# Generated by FakeRAM 2.0
VERSION 5.7 ;
BUSBITCHARS "[]" ;
PROPERTYDEFINITIONS
  MACRO width INTEGER ;
  MACRO depth INTEGER ;
  MACRO banks INTEGER ;
END PROPERTYDEFINITIONS
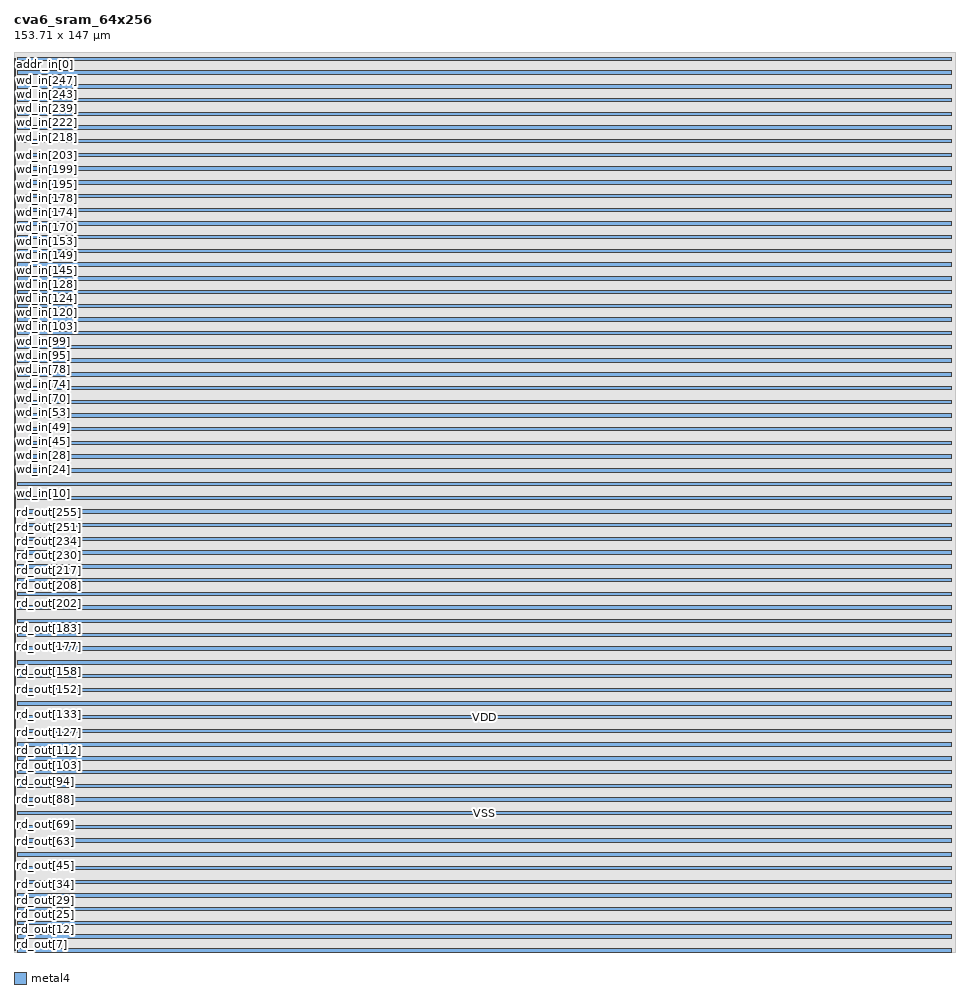
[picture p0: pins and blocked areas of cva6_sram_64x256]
MACRO cva6_sram_64x256
  PROPERTY width 256 ;
  PROPERTY depth 64 ;
  PROPERTY banks 1 ;
  FOREIGN cva6_sram_64x256 0 0 ;
  SYMMETRY X Y R90 ;
  SIZE 153.7100 BY 147.0000 ;
  CLASS BLOCK ;
  PIN rd_out[0]
    DIRECTION OUTPUT ;
    USE SIGNAL ;
    PORT
      LAYER metal4 ;
      RECT 0.00000 0.28000 0.21000 0.42000 ;
    END
  END rd_out[0]
  PIN rd_out[1]
    DIRECTION OUTPUT ;
    USE SIGNAL ;
    PORT
      LAYER metal4 ;
      RECT 0.00000 0.56000 0.21000 0.70000 ;
    END
  END rd_out[1]
  PIN rd_out[2]
    DIRECTION OUTPUT ;
    USE SIGNAL ;
    PORT
      LAYER metal4 ;
      RECT 0.00000 0.84000 0.21000 0.98000 ;
    END
  END rd_out[2]
  PIN rd_out[3]
    DIRECTION OUTPUT ;
    USE SIGNAL ;
    PORT
      LAYER metal4 ;
      RECT 0.00000 1.12000 0.21000 1.26000 ;
    END
  END rd_out[3]
  PIN rd_out[4]
    DIRECTION OUTPUT ;
    USE SIGNAL ;
    PORT
      LAYER metal4 ;
      RECT 0.00000 1.40000 0.21000 1.54000 ;
    END
  END rd_out[4]
  PIN rd_out[5]
    DIRECTION OUTPUT ;
    USE SIGNAL ;
    PORT
      LAYER metal4 ;
      RECT 0.00000 1.68000 0.21000 1.82000 ;
    END
  END rd_out[5]
  PIN rd_out[6]
    DIRECTION OUTPUT ;
    USE SIGNAL ;
    PORT
      LAYER metal4 ;
      RECT 0.00000 1.96000 0.21000 2.10000 ;
    END
  END rd_out[6]
  PIN rd_out[7]
    DIRECTION OUTPUT ;
    USE SIGNAL ;
    PORT
      LAYER metal4 ;
      RECT 0.00000 2.24000 0.21000 2.38000 ;
    END
  END rd_out[7]
  PIN rd_out[8]
    DIRECTION OUTPUT ;
    USE SIGNAL ;
    PORT
      LAYER metal4 ;
      RECT 0.00000 2.52000 0.21000 2.66000 ;
    END
  END rd_out[8]
  PIN rd_out[9]
    DIRECTION OUTPUT ;
    USE SIGNAL ;
    PORT
      LAYER metal4 ;
      RECT 0.00000 2.80000 0.21000 2.94000 ;
    END
  END rd_out[9]
  PIN rd_out[10]
    DIRECTION OUTPUT ;
    USE SIGNAL ;
    PORT
      LAYER metal4 ;
      RECT 0.00000 3.08000 0.21000 3.22000 ;
    END
  END rd_out[10]
  PIN rd_out[11]
    DIRECTION OUTPUT ;
    USE SIGNAL ;
    PORT
      LAYER metal4 ;
      RECT 0.00000 3.36000 0.21000 3.50000 ;
    END
  END rd_out[11]
  PIN rd_out[12]
    DIRECTION OUTPUT ;
    USE SIGNAL ;
    PORT
      LAYER metal4 ;
      RECT 0.00000 3.64000 0.21000 3.78000 ;
    END
  END rd_out[12]
  PIN rd_out[13]
    DIRECTION OUTPUT ;
    USE SIGNAL ;
    PORT
      LAYER metal4 ;
      RECT 0.00000 3.92000 0.21000 4.06000 ;
    END
  END rd_out[13]
  PIN rd_out[14]
    DIRECTION OUTPUT ;
    USE SIGNAL ;
    PORT
      LAYER metal4 ;
      RECT 0.00000 4.20000 0.21000 4.34000 ;
    END
  END rd_out[14]
  PIN rd_out[15]
    DIRECTION OUTPUT ;
    USE SIGNAL ;
    PORT
      LAYER metal4 ;
      RECT 0.00000 4.48000 0.21000 4.62000 ;
    END
  END rd_out[15]
  PIN rd_out[16]
    DIRECTION OUTPUT ;
    USE SIGNAL ;
    PORT
      LAYER metal4 ;
      RECT 0.00000 4.76000 0.21000 4.90000 ;
    END
  END rd_out[16]
  PIN rd_out[17]
    DIRECTION OUTPUT ;
    USE SIGNAL ;
    PORT
      LAYER metal4 ;
      RECT 0.00000 5.04000 0.21000 5.18000 ;
    END
  END rd_out[17]
  PIN rd_out[18]
    DIRECTION OUTPUT ;
    USE SIGNAL ;
    PORT
      LAYER metal4 ;
      RECT 0.00000 5.32000 0.21000 5.46000 ;
    END
  END rd_out[18]
  PIN rd_out[19]
    DIRECTION OUTPUT ;
    USE SIGNAL ;
    PORT
      LAYER metal4 ;
      RECT 0.00000 5.60000 0.21000 5.74000 ;
    END
  END rd_out[19]
  PIN rd_out[20]
    DIRECTION OUTPUT ;
    USE SIGNAL ;
    PORT
      LAYER metal4 ;
      RECT 0.00000 5.88000 0.21000 6.02000 ;
    END
  END rd_out[20]
  PIN rd_out[21]
    DIRECTION OUTPUT ;
    USE SIGNAL ;
    PORT
      LAYER metal4 ;
      RECT 0.00000 6.16000 0.21000 6.30000 ;
    END
  END rd_out[21]
  PIN rd_out[22]
    DIRECTION OUTPUT ;
    USE SIGNAL ;
    PORT
      LAYER metal4 ;
      RECT 0.00000 6.44000 0.21000 6.58000 ;
    END
  END rd_out[22]
  PIN rd_out[23]
    DIRECTION OUTPUT ;
    USE SIGNAL ;
    PORT
      LAYER metal4 ;
      RECT 0.00000 6.72000 0.21000 6.86000 ;
    END
  END rd_out[23]
  PIN rd_out[24]
    DIRECTION OUTPUT ;
    USE SIGNAL ;
    PORT
      LAYER metal4 ;
      RECT 0.00000 7.00000 0.21000 7.14000 ;
    END
  END rd_out[24]
  PIN rd_out[25]
    DIRECTION OUTPUT ;
    USE SIGNAL ;
    PORT
      LAYER metal4 ;
      RECT 0.00000 7.28000 0.21000 7.42000 ;
    END
  END rd_out[25]
  PIN rd_out[26]
    DIRECTION OUTPUT ;
    USE SIGNAL ;
    PORT
      LAYER metal4 ;
      RECT 0.00000 7.56000 0.21000 7.70000 ;
    END
  END rd_out[26]
  PIN rd_out[27]
    DIRECTION OUTPUT ;
    USE SIGNAL ;
    PORT
      LAYER metal4 ;
      RECT 0.00000 7.84000 0.21000 7.98000 ;
    END
  END rd_out[27]
  PIN rd_out[28]
    DIRECTION OUTPUT ;
    USE SIGNAL ;
    PORT
      LAYER metal4 ;
      RECT 0.00000 8.12000 0.21000 8.26000 ;
    END
  END rd_out[28]
  PIN rd_out[29]
    DIRECTION OUTPUT ;
    USE SIGNAL ;
    PORT
      LAYER metal4 ;
      RECT 0.00000 8.40000 0.21000 8.54000 ;
    END
  END rd_out[29]
  PIN rd_out[30]
    DIRECTION OUTPUT ;
    USE SIGNAL ;
    PORT
      LAYER metal4 ;
      RECT 0.00000 8.68000 0.21000 8.82000 ;
    END
  END rd_out[30]
  PIN rd_out[31]
    DIRECTION OUTPUT ;
    USE SIGNAL ;
    PORT
      LAYER metal4 ;
      RECT 0.00000 8.96000 0.21000 9.10000 ;
    END
  END rd_out[31]
  PIN rd_out[32]
    DIRECTION OUTPUT ;
    USE SIGNAL ;
    PORT
      LAYER metal4 ;
      RECT 0.00000 9.24000 0.21000 9.38000 ;
    END
  END rd_out[32]
  PIN rd_out[33]
    DIRECTION OUTPUT ;
    USE SIGNAL ;
    PORT
      LAYER metal4 ;
      RECT 0.00000 9.52000 0.21000 9.66000 ;
    END
  END rd_out[33]
  PIN rd_out[34]
    DIRECTION OUTPUT ;
    USE SIGNAL ;
    PORT
      LAYER metal4 ;
      RECT 0.00000 9.80000 0.21000 9.94000 ;
    END
  END rd_out[34]
  PIN rd_out[35]
    DIRECTION OUTPUT ;
    USE SIGNAL ;
    PORT
      LAYER metal4 ;
      RECT 0.00000 10.08000 0.21000 10.22000 ;
    END
  END rd_out[35]
  PIN rd_out[36]
    DIRECTION OUTPUT ;
    USE SIGNAL ;
    PORT
      LAYER metal4 ;
      RECT 0.00000 10.36000 0.21000 10.50000 ;
    END
  END rd_out[36]
  PIN rd_out[37]
    DIRECTION OUTPUT ;
    USE SIGNAL ;
    PORT
      LAYER metal4 ;
      RECT 0.00000 10.64000 0.21000 10.78000 ;
    END
  END rd_out[37]
  PIN rd_out[38]
    DIRECTION OUTPUT ;
    USE SIGNAL ;
    PORT
      LAYER metal4 ;
      RECT 0.00000 10.92000 0.21000 11.06000 ;
    END
  END rd_out[38]
  PIN rd_out[39]
    DIRECTION OUTPUT ;
    USE SIGNAL ;
    PORT
      LAYER metal4 ;
      RECT 0.00000 11.20000 0.21000 11.34000 ;
    END
  END rd_out[39]
  PIN rd_out[40]
    DIRECTION OUTPUT ;
    USE SIGNAL ;
    PORT
      LAYER metal4 ;
      RECT 0.00000 11.48000 0.21000 11.62000 ;
    END
  END rd_out[40]
  PIN rd_out[41]
    DIRECTION OUTPUT ;
    USE SIGNAL ;
    PORT
      LAYER metal4 ;
      RECT 0.00000 11.76000 0.21000 11.90000 ;
    END
  END rd_out[41]
  PIN rd_out[42]
    DIRECTION OUTPUT ;
    USE SIGNAL ;
    PORT
      LAYER metal4 ;
      RECT 0.00000 12.04000 0.21000 12.18000 ;
    END
  END rd_out[42]
  PIN rd_out[43]
    DIRECTION OUTPUT ;
    USE SIGNAL ;
    PORT
      LAYER metal4 ;
      RECT 0.00000 12.32000 0.21000 12.46000 ;
    END
  END rd_out[43]
  PIN rd_out[44]
    DIRECTION OUTPUT ;
    USE SIGNAL ;
    PORT
      LAYER metal4 ;
      RECT 0.00000 12.60000 0.21000 12.74000 ;
    END
  END rd_out[44]
  PIN rd_out[45]
    DIRECTION OUTPUT ;
    USE SIGNAL ;
    PORT
      LAYER metal4 ;
      RECT 0.00000 12.88000 0.21000 13.02000 ;
    END
  END rd_out[45]
  PIN rd_out[46]
    DIRECTION OUTPUT ;
    USE SIGNAL ;
    PORT
      LAYER metal4 ;
      RECT 0.00000 13.16000 0.21000 13.30000 ;
    END
  END rd_out[46]
  PIN rd_out[47]
    DIRECTION OUTPUT ;
    USE SIGNAL ;
    PORT
      LAYER metal4 ;
      RECT 0.00000 13.44000 0.21000 13.58000 ;
    END
  END rd_out[47]
  PIN rd_out[48]
    DIRECTION OUTPUT ;
    USE SIGNAL ;
    PORT
      LAYER metal4 ;
      RECT 0.00000 13.72000 0.21000 13.86000 ;
    END
  END rd_out[48]
  PIN rd_out[49]
    DIRECTION OUTPUT ;
    USE SIGNAL ;
    PORT
      LAYER metal4 ;
      RECT 0.00000 14.00000 0.21000 14.14000 ;
    END
  END rd_out[49]
  PIN rd_out[50]
    DIRECTION OUTPUT ;
    USE SIGNAL ;
    PORT
      LAYER metal4 ;
      RECT 0.00000 14.28000 0.21000 14.42000 ;
    END
  END rd_out[50]
  PIN rd_out[51]
    DIRECTION OUTPUT ;
    USE SIGNAL ;
    PORT
      LAYER metal4 ;
      RECT 0.00000 14.56000 0.21000 14.70000 ;
    END
  END rd_out[51]
  PIN rd_out[52]
    DIRECTION OUTPUT ;
    USE SIGNAL ;
    PORT
      LAYER metal4 ;
      RECT 0.00000 14.84000 0.21000 14.98000 ;
    END
  END rd_out[52]
  PIN rd_out[53]
    DIRECTION OUTPUT ;
    USE SIGNAL ;
    PORT
      LAYER metal4 ;
      RECT 0.00000 15.12000 0.21000 15.26000 ;
    END
  END rd_out[53]
  PIN rd_out[54]
    DIRECTION OUTPUT ;
    USE SIGNAL ;
    PORT
      LAYER metal4 ;
      RECT 0.00000 15.40000 0.21000 15.54000 ;
    END
  END rd_out[54]
  PIN rd_out[55]
    DIRECTION OUTPUT ;
    USE SIGNAL ;
    PORT
      LAYER metal4 ;
      RECT 0.00000 15.68000 0.21000 15.82000 ;
    END
  END rd_out[55]
  PIN rd_out[56]
    DIRECTION OUTPUT ;
    USE SIGNAL ;
    PORT
      LAYER metal4 ;
      RECT 0.00000 15.96000 0.21000 16.10000 ;
    END
  END rd_out[56]
  PIN rd_out[57]
    DIRECTION OUTPUT ;
    USE SIGNAL ;
    PORT
      LAYER metal4 ;
      RECT 0.00000 16.24000 0.21000 16.38000 ;
    END
  END rd_out[57]
  PIN rd_out[58]
    DIRECTION OUTPUT ;
    USE SIGNAL ;
    PORT
      LAYER metal4 ;
      RECT 0.00000 16.52000 0.21000 16.66000 ;
    END
  END rd_out[58]
  PIN rd_out[59]
    DIRECTION OUTPUT ;
    USE SIGNAL ;
    PORT
      LAYER metal4 ;
      RECT 0.00000 16.80000 0.21000 16.94000 ;
    END
  END rd_out[59]
  PIN rd_out[60]
    DIRECTION OUTPUT ;
    USE SIGNAL ;
    PORT
      LAYER metal4 ;
      RECT 0.00000 17.08000 0.21000 17.22000 ;
    END
  END rd_out[60]
  PIN rd_out[61]
    DIRECTION OUTPUT ;
    USE SIGNAL ;
    PORT
      LAYER metal4 ;
      RECT 0.00000 17.36000 0.21000 17.50000 ;
    END
  END rd_out[61]
  PIN rd_out[62]
    DIRECTION OUTPUT ;
    USE SIGNAL ;
    PORT
      LAYER metal4 ;
      RECT 0.00000 17.64000 0.21000 17.78000 ;
    END
  END rd_out[62]
  PIN rd_out[63]
    DIRECTION OUTPUT ;
    USE SIGNAL ;
    PORT
      LAYER metal4 ;
      RECT 0.00000 17.92000 0.21000 18.06000 ;
    END
  END rd_out[63]
  PIN rd_out[64]
    DIRECTION OUTPUT ;
    USE SIGNAL ;
    PORT
      LAYER metal4 ;
      RECT 0.00000 18.20000 0.21000 18.34000 ;
    END
  END rd_out[64]
  PIN rd_out[65]
    DIRECTION OUTPUT ;
    USE SIGNAL ;
    PORT
      LAYER metal4 ;
      RECT 0.00000 18.48000 0.21000 18.62000 ;
    END
  END rd_out[65]
  PIN rd_out[66]
    DIRECTION OUTPUT ;
    USE SIGNAL ;
    PORT
      LAYER metal4 ;
      RECT 0.00000 18.76000 0.21000 18.90000 ;
    END
  END rd_out[66]
  PIN rd_out[67]
    DIRECTION OUTPUT ;
    USE SIGNAL ;
    PORT
      LAYER metal4 ;
      RECT 0.00000 19.04000 0.21000 19.18000 ;
    END
  END rd_out[67]
  PIN rd_out[68]
    DIRECTION OUTPUT ;
    USE SIGNAL ;
    PORT
      LAYER metal4 ;
      RECT 0.00000 19.32000 0.21000 19.46000 ;
    END
  END rd_out[68]
  PIN rd_out[69]
    DIRECTION OUTPUT ;
    USE SIGNAL ;
    PORT
      LAYER metal4 ;
      RECT 0.00000 19.60000 0.21000 19.74000 ;
    END
  END rd_out[69]
  PIN rd_out[70]
    DIRECTION OUTPUT ;
    USE SIGNAL ;
    PORT
      LAYER metal4 ;
      RECT 0.00000 19.88000 0.21000 20.02000 ;
    END
  END rd_out[70]
  PIN rd_out[71]
    DIRECTION OUTPUT ;
    USE SIGNAL ;
    PORT
      LAYER metal4 ;
      RECT 0.00000 20.16000 0.21000 20.30000 ;
    END
  END rd_out[71]
  PIN rd_out[72]
    DIRECTION OUTPUT ;
    USE SIGNAL ;
    PORT
      LAYER metal4 ;
      RECT 0.00000 20.44000 0.21000 20.58000 ;
    END
  END rd_out[72]
  PIN rd_out[73]
    DIRECTION OUTPUT ;
    USE SIGNAL ;
    PORT
      LAYER metal4 ;
      RECT 0.00000 20.72000 0.21000 20.86000 ;
    END
  END rd_out[73]
  PIN rd_out[74]
    DIRECTION OUTPUT ;
    USE SIGNAL ;
    PORT
      LAYER metal4 ;
      RECT 0.00000 21.00000 0.21000 21.14000 ;
    END
  END rd_out[74]
  PIN rd_out[75]
    DIRECTION OUTPUT ;
    USE SIGNAL ;
    PORT
      LAYER metal4 ;
      RECT 0.00000 21.28000 0.21000 21.42000 ;
    END
  END rd_out[75]
  PIN rd_out[76]
    DIRECTION OUTPUT ;
    USE SIGNAL ;
    PORT
      LAYER metal4 ;
      RECT 0.00000 21.56000 0.21000 21.70000 ;
    END
  END rd_out[76]
  PIN rd_out[77]
    DIRECTION OUTPUT ;
    USE SIGNAL ;
    PORT
      LAYER metal4 ;
      RECT 0.00000 21.84000 0.21000 21.98000 ;
    END
  END rd_out[77]
  PIN rd_out[78]
    DIRECTION OUTPUT ;
    USE SIGNAL ;
    PORT
      LAYER metal4 ;
      RECT 0.00000 22.12000 0.21000 22.26000 ;
    END
  END rd_out[78]
  PIN rd_out[79]
    DIRECTION OUTPUT ;
    USE SIGNAL ;
    PORT
      LAYER metal4 ;
      RECT 0.00000 22.40000 0.21000 22.54000 ;
    END
  END rd_out[79]
  PIN rd_out[80]
    DIRECTION OUTPUT ;
    USE SIGNAL ;
    PORT
      LAYER metal4 ;
      RECT 0.00000 22.68000 0.21000 22.82000 ;
    END
  END rd_out[80]
  PIN rd_out[81]
    DIRECTION OUTPUT ;
    USE SIGNAL ;
    PORT
      LAYER metal4 ;
      RECT 0.00000 22.96000 0.21000 23.10000 ;
    END
  END rd_out[81]
  PIN rd_out[82]
    DIRECTION OUTPUT ;
    USE SIGNAL ;
    PORT
      LAYER metal4 ;
      RECT 0.00000 23.24000 0.21000 23.38000 ;
    END
  END rd_out[82]
  PIN rd_out[83]
    DIRECTION OUTPUT ;
    USE SIGNAL ;
    PORT
      LAYER metal4 ;
      RECT 0.00000 23.52000 0.21000 23.66000 ;
    END
  END rd_out[83]
  PIN rd_out[84]
    DIRECTION OUTPUT ;
    USE SIGNAL ;
    PORT
      LAYER metal4 ;
      RECT 0.00000 23.80000 0.21000 23.94000 ;
    END
  END rd_out[84]
  PIN rd_out[85]
    DIRECTION OUTPUT ;
    USE SIGNAL ;
    PORT
      LAYER metal4 ;
      RECT 0.00000 24.08000 0.21000 24.22000 ;
    END
  END rd_out[85]
  PIN rd_out[86]
    DIRECTION OUTPUT ;
    USE SIGNAL ;
    PORT
      LAYER metal4 ;
      RECT 0.00000 24.36000 0.21000 24.50000 ;
    END
  END rd_out[86]
  PIN rd_out[87]
    DIRECTION OUTPUT ;
    USE SIGNAL ;
    PORT
      LAYER metal4 ;
      RECT 0.00000 24.64000 0.21000 24.78000 ;
    END
  END rd_out[87]
  PIN rd_out[88]
    DIRECTION OUTPUT ;
    USE SIGNAL ;
    PORT
      LAYER metal4 ;
      RECT 0.00000 24.92000 0.21000 25.06000 ;
    END
  END rd_out[88]
  PIN rd_out[89]
    DIRECTION OUTPUT ;
    USE SIGNAL ;
    PORT
      LAYER metal4 ;
      RECT 0.00000 25.20000 0.21000 25.34000 ;
    END
  END rd_out[89]
  PIN rd_out[90]
    DIRECTION OUTPUT ;
    USE SIGNAL ;
    PORT
      LAYER metal4 ;
      RECT 0.00000 25.48000 0.21000 25.62000 ;
    END
  END rd_out[90]
  PIN rd_out[91]
    DIRECTION OUTPUT ;
    USE SIGNAL ;
    PORT
      LAYER metal4 ;
      RECT 0.00000 25.76000 0.21000 25.90000 ;
    END
  END rd_out[91]
  PIN rd_out[92]
    DIRECTION OUTPUT ;
    USE SIGNAL ;
    PORT
      LAYER metal4 ;
      RECT 0.00000 26.04000 0.21000 26.18000 ;
    END
  END rd_out[92]
  PIN rd_out[93]
    DIRECTION OUTPUT ;
    USE SIGNAL ;
    PORT
      LAYER metal4 ;
      RECT 0.00000 26.32000 0.21000 26.46000 ;
    END
  END rd_out[93]
  PIN rd_out[94]
    DIRECTION OUTPUT ;
    USE SIGNAL ;
    PORT
      LAYER metal4 ;
      RECT 0.00000 26.60000 0.21000 26.74000 ;
    END
  END rd_out[94]
  PIN rd_out[95]
    DIRECTION OUTPUT ;
    USE SIGNAL ;
    PORT
      LAYER metal4 ;
      RECT 0.00000 26.88000 0.21000 27.02000 ;
    END
  END rd_out[95]
  PIN rd_out[96]
    DIRECTION OUTPUT ;
    USE SIGNAL ;
    PORT
      LAYER metal4 ;
      RECT 0.00000 27.16000 0.21000 27.30000 ;
    END
  END rd_out[96]
  PIN rd_out[97]
    DIRECTION OUTPUT ;
    USE SIGNAL ;
    PORT
      LAYER metal4 ;
      RECT 0.00000 27.44000 0.21000 27.58000 ;
    END
  END rd_out[97]
  PIN rd_out[98]
    DIRECTION OUTPUT ;
    USE SIGNAL ;
    PORT
      LAYER metal4 ;
      RECT 0.00000 27.72000 0.21000 27.86000 ;
    END
  END rd_out[98]
  PIN rd_out[99]
    DIRECTION OUTPUT ;
    USE SIGNAL ;
    PORT
      LAYER metal4 ;
      RECT 0.00000 28.00000 0.21000 28.14000 ;
    END
  END rd_out[99]
  PIN rd_out[100]
    DIRECTION OUTPUT ;
    USE SIGNAL ;
    PORT
      LAYER metal4 ;
      RECT 0.00000 28.28000 0.21000 28.42000 ;
    END
  END rd_out[100]
  PIN rd_out[101]
    DIRECTION OUTPUT ;
    USE SIGNAL ;
    PORT
      LAYER metal4 ;
      RECT 0.00000 28.56000 0.21000 28.70000 ;
    END
  END rd_out[101]
  PIN rd_out[102]
    DIRECTION OUTPUT ;
    USE SIGNAL ;
    PORT
      LAYER metal4 ;
      RECT 0.00000 28.84000 0.21000 28.98000 ;
    END
  END rd_out[102]
  PIN rd_out[103]
    DIRECTION OUTPUT ;
    USE SIGNAL ;
    PORT
      LAYER metal4 ;
      RECT 0.00000 29.12000 0.21000 29.26000 ;
    END
  END rd_out[103]
  PIN rd_out[104]
    DIRECTION OUTPUT ;
    USE SIGNAL ;
    PORT
      LAYER metal4 ;
      RECT 0.00000 29.40000 0.21000 29.54000 ;
    END
  END rd_out[104]
  PIN rd_out[105]
    DIRECTION OUTPUT ;
    USE SIGNAL ;
    PORT
      LAYER metal4 ;
      RECT 0.00000 29.68000 0.21000 29.82000 ;
    END
  END rd_out[105]
  PIN rd_out[106]
    DIRECTION OUTPUT ;
    USE SIGNAL ;
    PORT
      LAYER metal4 ;
      RECT 0.00000 29.96000 0.21000 30.10000 ;
    END
  END rd_out[106]
  PIN rd_out[107]
    DIRECTION OUTPUT ;
    USE SIGNAL ;
    PORT
      LAYER metal4 ;
      RECT 0.00000 30.24000 0.21000 30.38000 ;
    END
  END rd_out[107]
  PIN rd_out[108]
    DIRECTION OUTPUT ;
    USE SIGNAL ;
    PORT
      LAYER metal4 ;
      RECT 0.00000 30.52000 0.21000 30.66000 ;
    END
  END rd_out[108]
  PIN rd_out[109]
    DIRECTION OUTPUT ;
    USE SIGNAL ;
    PORT
      LAYER metal4 ;
      RECT 0.00000 30.80000 0.21000 30.94000 ;
    END
  END rd_out[109]
  PIN rd_out[110]
    DIRECTION OUTPUT ;
    USE SIGNAL ;
    PORT
      LAYER metal4 ;
      RECT 0.00000 31.08000 0.21000 31.22000 ;
    END
  END rd_out[110]
  PIN rd_out[111]
    DIRECTION OUTPUT ;
    USE SIGNAL ;
    PORT
      LAYER metal4 ;
      RECT 0.00000 31.36000 0.21000 31.50000 ;
    END
  END rd_out[111]
  PIN rd_out[112]
    DIRECTION OUTPUT ;
    USE SIGNAL ;
    PORT
      LAYER metal4 ;
      RECT 0.00000 31.64000 0.21000 31.78000 ;
    END
  END rd_out[112]
  PIN rd_out[113]
    DIRECTION OUTPUT ;
    USE SIGNAL ;
    PORT
      LAYER metal4 ;
      RECT 0.00000 31.92000 0.21000 32.06000 ;
    END
  END rd_out[113]
  PIN rd_out[114]
    DIRECTION OUTPUT ;
    USE SIGNAL ;
    PORT
      LAYER metal4 ;
      RECT 0.00000 32.20000 0.21000 32.34000 ;
    END
  END rd_out[114]
  PIN rd_out[115]
    DIRECTION OUTPUT ;
    USE SIGNAL ;
    PORT
      LAYER metal4 ;
      RECT 0.00000 32.48000 0.21000 32.62000 ;
    END
  END rd_out[115]
  PIN rd_out[116]
    DIRECTION OUTPUT ;
    USE SIGNAL ;
    PORT
      LAYER metal4 ;
      RECT 0.00000 32.76000 0.21000 32.90000 ;
    END
  END rd_out[116]
  PIN rd_out[117]
    DIRECTION OUTPUT ;
    USE SIGNAL ;
    PORT
      LAYER metal4 ;
      RECT 0.00000 33.04000 0.21000 33.18000 ;
    END
  END rd_out[117]
  PIN rd_out[118]
    DIRECTION OUTPUT ;
    USE SIGNAL ;
    PORT
      LAYER metal4 ;
      RECT 0.00000 33.32000 0.21000 33.46000 ;
    END
  END rd_out[118]
  PIN rd_out[119]
    DIRECTION OUTPUT ;
    USE SIGNAL ;
    PORT
      LAYER metal4 ;
      RECT 0.00000 33.60000 0.21000 33.74000 ;
    END
  END rd_out[119]
  PIN rd_out[120]
    DIRECTION OUTPUT ;
    USE SIGNAL ;
    PORT
      LAYER metal4 ;
      RECT 0.00000 33.88000 0.21000 34.02000 ;
    END
  END rd_out[120]
  PIN rd_out[121]
    DIRECTION OUTPUT ;
    USE SIGNAL ;
    PORT
      LAYER metal4 ;
      RECT 0.00000 34.16000 0.21000 34.30000 ;
    END
  END rd_out[121]
  PIN rd_out[122]
    DIRECTION OUTPUT ;
    USE SIGNAL ;
    PORT
      LAYER metal4 ;
      RECT 0.00000 34.44000 0.21000 34.58000 ;
    END
  END rd_out[122]
  PIN rd_out[123]
    DIRECTION OUTPUT ;
    USE SIGNAL ;
    PORT
      LAYER metal4 ;
      RECT 0.00000 34.72000 0.21000 34.86000 ;
    END
  END rd_out[123]
  PIN rd_out[124]
    DIRECTION OUTPUT ;
    USE SIGNAL ;
    PORT
      LAYER metal4 ;
      RECT 0.00000 35.00000 0.21000 35.14000 ;
    END
  END rd_out[124]
  PIN rd_out[125]
    DIRECTION OUTPUT ;
    USE SIGNAL ;
    PORT
      LAYER metal4 ;
      RECT 0.00000 35.28000 0.21000 35.42000 ;
    END
  END rd_out[125]
  PIN rd_out[126]
    DIRECTION OUTPUT ;
    USE SIGNAL ;
    PORT
      LAYER metal4 ;
      RECT 0.00000 35.56000 0.21000 35.70000 ;
    END
  END rd_out[126]
  PIN rd_out[127]
    DIRECTION OUTPUT ;
    USE SIGNAL ;
    PORT
      LAYER metal4 ;
      RECT 0.00000 35.84000 0.21000 35.98000 ;
    END
  END rd_out[127]
  PIN rd_out[128]
    DIRECTION OUTPUT ;
    USE SIGNAL ;
    PORT
      LAYER metal4 ;
      RECT 0.00000 36.12000 0.21000 36.26000 ;
    END
  END rd_out[128]
  PIN rd_out[129]
    DIRECTION OUTPUT ;
    USE SIGNAL ;
    PORT
      LAYER metal4 ;
      RECT 0.00000 36.40000 0.21000 36.54000 ;
    END
  END rd_out[129]
  PIN rd_out[130]
    DIRECTION OUTPUT ;
    USE SIGNAL ;
    PORT
      LAYER metal4 ;
      RECT 0.00000 36.68000 0.21000 36.82000 ;
    END
  END rd_out[130]
  PIN rd_out[131]
    DIRECTION OUTPUT ;
    USE SIGNAL ;
    PORT
      LAYER metal4 ;
      RECT 0.00000 36.96000 0.21000 37.10000 ;
    END
  END rd_out[131]
  PIN rd_out[132]
    DIRECTION OUTPUT ;
    USE SIGNAL ;
    PORT
      LAYER metal4 ;
      RECT 0.00000 37.24000 0.21000 37.38000 ;
    END
  END rd_out[132]
  PIN rd_out[133]
    DIRECTION OUTPUT ;
    USE SIGNAL ;
    PORT
      LAYER metal4 ;
      RECT 0.00000 37.52000 0.21000 37.66000 ;
    END
  END rd_out[133]
  PIN rd_out[134]
    DIRECTION OUTPUT ;
    USE SIGNAL ;
    PORT
      LAYER metal4 ;
      RECT 0.00000 37.80000 0.21000 37.94000 ;
    END
  END rd_out[134]
  PIN rd_out[135]
    DIRECTION OUTPUT ;
    USE SIGNAL ;
    PORT
      LAYER metal4 ;
      RECT 0.00000 38.08000 0.21000 38.22000 ;
    END
  END rd_out[135]
  PIN rd_out[136]
    DIRECTION OUTPUT ;
    USE SIGNAL ;
    PORT
      LAYER metal4 ;
      RECT 0.00000 38.36000 0.21000 38.50000 ;
    END
  END rd_out[136]
  PIN rd_out[137]
    DIRECTION OUTPUT ;
    USE SIGNAL ;
    PORT
      LAYER metal4 ;
      RECT 0.00000 38.64000 0.21000 38.78000 ;
    END
  END rd_out[137]
  PIN rd_out[138]
    DIRECTION OUTPUT ;
    USE SIGNAL ;
    PORT
      LAYER metal4 ;
      RECT 0.00000 38.92000 0.21000 39.06000 ;
    END
  END rd_out[138]
  PIN rd_out[139]
    DIRECTION OUTPUT ;
    USE SIGNAL ;
    PORT
      LAYER metal4 ;
      RECT 0.00000 39.20000 0.21000 39.34000 ;
    END
  END rd_out[139]
  PIN rd_out[140]
    DIRECTION OUTPUT ;
    USE SIGNAL ;
    PORT
      LAYER metal4 ;
      RECT 0.00000 39.48000 0.21000 39.62000 ;
    END
  END rd_out[140]
  PIN rd_out[141]
    DIRECTION OUTPUT ;
    USE SIGNAL ;
    PORT
      LAYER metal4 ;
      RECT 0.00000 39.76000 0.21000 39.90000 ;
    END
  END rd_out[141]
  PIN rd_out[142]
    DIRECTION OUTPUT ;
    USE SIGNAL ;
    PORT
      LAYER metal4 ;
      RECT 0.00000 40.04000 0.21000 40.18000 ;
    END
  END rd_out[142]
  PIN rd_out[143]
    DIRECTION OUTPUT ;
    USE SIGNAL ;
    PORT
      LAYER metal4 ;
      RECT 0.00000 40.32000 0.21000 40.46000 ;
    END
  END rd_out[143]
  PIN rd_out[144]
    DIRECTION OUTPUT ;
    USE SIGNAL ;
    PORT
      LAYER metal4 ;
      RECT 0.00000 40.60000 0.21000 40.74000 ;
    END
  END rd_out[144]
  PIN rd_out[145]
    DIRECTION OUTPUT ;
    USE SIGNAL ;
    PORT
      LAYER metal4 ;
      RECT 0.00000 40.88000 0.21000 41.02000 ;
    END
  END rd_out[145]
  PIN rd_out[146]
    DIRECTION OUTPUT ;
    USE SIGNAL ;
    PORT
      LAYER metal4 ;
      RECT 0.00000 41.16000 0.21000 41.30000 ;
    END
  END rd_out[146]
  PIN rd_out[147]
    DIRECTION OUTPUT ;
    USE SIGNAL ;
    PORT
      LAYER metal4 ;
      RECT 0.00000 41.44000 0.21000 41.58000 ;
    END
  END rd_out[147]
  PIN rd_out[148]
    DIRECTION OUTPUT ;
    USE SIGNAL ;
    PORT
      LAYER metal4 ;
      RECT 0.00000 41.72000 0.21000 41.86000 ;
    END
  END rd_out[148]
  PIN rd_out[149]
    DIRECTION OUTPUT ;
    USE SIGNAL ;
    PORT
      LAYER metal4 ;
      RECT 0.00000 42.00000 0.21000 42.14000 ;
    END
  END rd_out[149]
  PIN rd_out[150]
    DIRECTION OUTPUT ;
    USE SIGNAL ;
    PORT
      LAYER metal4 ;
      RECT 0.00000 42.28000 0.21000 42.42000 ;
    END
  END rd_out[150]
  PIN rd_out[151]
    DIRECTION OUTPUT ;
    USE SIGNAL ;
    PORT
      LAYER metal4 ;
      RECT 0.00000 42.56000 0.21000 42.70000 ;
    END
  END rd_out[151]
  PIN rd_out[152]
    DIRECTION OUTPUT ;
    USE SIGNAL ;
    PORT
      LAYER metal4 ;
      RECT 0.00000 42.84000 0.21000 42.98000 ;
    END
  END rd_out[152]
  PIN rd_out[153]
    DIRECTION OUTPUT ;
    USE SIGNAL ;
    PORT
      LAYER metal4 ;
      RECT 0.00000 43.12000 0.21000 43.26000 ;
    END
  END rd_out[153]
  PIN rd_out[154]
    DIRECTION OUTPUT ;
    USE SIGNAL ;
    PORT
      LAYER metal4 ;
      RECT 0.00000 43.40000 0.21000 43.54000 ;
    END
  END rd_out[154]
  PIN rd_out[155]
    DIRECTION OUTPUT ;
    USE SIGNAL ;
    PORT
      LAYER metal4 ;
      RECT 0.00000 43.68000 0.21000 43.82000 ;
    END
  END rd_out[155]
  PIN rd_out[156]
    DIRECTION OUTPUT ;
    USE SIGNAL ;
    PORT
      LAYER metal4 ;
      RECT 0.00000 43.96000 0.21000 44.10000 ;
    END
  END rd_out[156]
  PIN rd_out[157]
    DIRECTION OUTPUT ;
    USE SIGNAL ;
    PORT
      LAYER metal4 ;
      RECT 0.00000 44.24000 0.21000 44.38000 ;
    END
  END rd_out[157]
  PIN rd_out[158]
    DIRECTION OUTPUT ;
    USE SIGNAL ;
    PORT
      LAYER metal4 ;
      RECT 0.00000 44.52000 0.21000 44.66000 ;
    END
  END rd_out[158]
  PIN rd_out[159]
    DIRECTION OUTPUT ;
    USE SIGNAL ;
    PORT
      LAYER metal4 ;
      RECT 0.00000 44.80000 0.21000 44.94000 ;
    END
  END rd_out[159]
  PIN rd_out[160]
    DIRECTION OUTPUT ;
    USE SIGNAL ;
    PORT
      LAYER metal4 ;
      RECT 0.00000 45.08000 0.21000 45.22000 ;
    END
  END rd_out[160]
  PIN rd_out[161]
    DIRECTION OUTPUT ;
    USE SIGNAL ;
    PORT
      LAYER metal4 ;
      RECT 0.00000 45.36000 0.21000 45.50000 ;
    END
  END rd_out[161]
  PIN rd_out[162]
    DIRECTION OUTPUT ;
    USE SIGNAL ;
    PORT
      LAYER metal4 ;
      RECT 0.00000 45.64000 0.21000 45.78000 ;
    END
  END rd_out[162]
  PIN rd_out[163]
    DIRECTION OUTPUT ;
    USE SIGNAL ;
    PORT
      LAYER metal4 ;
      RECT 0.00000 45.92000 0.21000 46.06000 ;
    END
  END rd_out[163]
  PIN rd_out[164]
    DIRECTION OUTPUT ;
    USE SIGNAL ;
    PORT
      LAYER metal4 ;
      RECT 0.00000 46.20000 0.21000 46.34000 ;
    END
  END rd_out[164]
  PIN rd_out[165]
    DIRECTION OUTPUT ;
    USE SIGNAL ;
    PORT
      LAYER metal4 ;
      RECT 0.00000 46.48000 0.21000 46.62000 ;
    END
  END rd_out[165]
  PIN rd_out[166]
    DIRECTION OUTPUT ;
    USE SIGNAL ;
    PORT
      LAYER metal4 ;
      RECT 0.00000 46.76000 0.21000 46.90000 ;
    END
  END rd_out[166]
  PIN rd_out[167]
    DIRECTION OUTPUT ;
    USE SIGNAL ;
    PORT
      LAYER metal4 ;
      RECT 0.00000 47.04000 0.21000 47.18000 ;
    END
  END rd_out[167]
  PIN rd_out[168]
    DIRECTION OUTPUT ;
    USE SIGNAL ;
    PORT
      LAYER metal4 ;
      RECT 0.00000 47.32000 0.21000 47.46000 ;
    END
  END rd_out[168]
  PIN rd_out[169]
    DIRECTION OUTPUT ;
    USE SIGNAL ;
    PORT
      LAYER metal4 ;
      RECT 0.00000 47.60000 0.21000 47.74000 ;
    END
  END rd_out[169]
  PIN rd_out[170]
    DIRECTION OUTPUT ;
    USE SIGNAL ;
    PORT
      LAYER metal4 ;
      RECT 0.00000 47.88000 0.21000 48.02000 ;
    END
  END rd_out[170]
  PIN rd_out[171]
    DIRECTION OUTPUT ;
    USE SIGNAL ;
    PORT
      LAYER metal4 ;
      RECT 0.00000 48.16000 0.21000 48.30000 ;
    END
  END rd_out[171]
  PIN rd_out[172]
    DIRECTION OUTPUT ;
    USE SIGNAL ;
    PORT
      LAYER metal4 ;
      RECT 0.00000 48.44000 0.21000 48.58000 ;
    END
  END rd_out[172]
  PIN rd_out[173]
    DIRECTION OUTPUT ;
    USE SIGNAL ;
    PORT
      LAYER metal4 ;
      RECT 0.00000 48.72000 0.21000 48.86000 ;
    END
  END rd_out[173]
  PIN rd_out[174]
    DIRECTION OUTPUT ;
    USE SIGNAL ;
    PORT
      LAYER metal4 ;
      RECT 0.00000 49.00000 0.21000 49.14000 ;
    END
  END rd_out[174]
  PIN rd_out[175]
    DIRECTION OUTPUT ;
    USE SIGNAL ;
    PORT
      LAYER metal4 ;
      RECT 0.00000 49.28000 0.21000 49.42000 ;
    END
  END rd_out[175]
  PIN rd_out[176]
    DIRECTION OUTPUT ;
    USE SIGNAL ;
    PORT
      LAYER metal4 ;
      RECT 0.00000 49.56000 0.21000 49.70000 ;
    END
  END rd_out[176]
  PIN rd_out[177]
    DIRECTION OUTPUT ;
    USE SIGNAL ;
    PORT
      LAYER metal4 ;
      RECT 0.00000 49.84000 0.21000 49.98000 ;
    END
  END rd_out[177]
  PIN rd_out[178]
    DIRECTION OUTPUT ;
    USE SIGNAL ;
    PORT
      LAYER metal4 ;
      RECT 0.00000 50.12000 0.21000 50.26000 ;
    END
  END rd_out[178]
  PIN rd_out[179]
    DIRECTION OUTPUT ;
    USE SIGNAL ;
    PORT
      LAYER metal4 ;
      RECT 0.00000 50.40000 0.21000 50.54000 ;
    END
  END rd_out[179]
  PIN rd_out[180]
    DIRECTION OUTPUT ;
    USE SIGNAL ;
    PORT
      LAYER metal4 ;
      RECT 0.00000 50.68000 0.21000 50.82000 ;
    END
  END rd_out[180]
  PIN rd_out[181]
    DIRECTION OUTPUT ;
    USE SIGNAL ;
    PORT
      LAYER metal4 ;
      RECT 0.00000 50.96000 0.21000 51.10000 ;
    END
  END rd_out[181]
  PIN rd_out[182]
    DIRECTION OUTPUT ;
    USE SIGNAL ;
    PORT
      LAYER metal4 ;
      RECT 0.00000 51.24000 0.21000 51.38000 ;
    END
  END rd_out[182]
  PIN rd_out[183]
    DIRECTION OUTPUT ;
    USE SIGNAL ;
    PORT
      LAYER metal4 ;
      RECT 0.00000 51.52000 0.21000 51.66000 ;
    END
  END rd_out[183]
  PIN rd_out[184]
    DIRECTION OUTPUT ;
    USE SIGNAL ;
    PORT
      LAYER metal4 ;
      RECT 0.00000 51.80000 0.21000 51.94000 ;
    END
  END rd_out[184]
  PIN rd_out[185]
    DIRECTION OUTPUT ;
    USE SIGNAL ;
    PORT
      LAYER metal4 ;
      RECT 0.00000 52.08000 0.21000 52.22000 ;
    END
  END rd_out[185]
  PIN rd_out[186]
    DIRECTION OUTPUT ;
    USE SIGNAL ;
    PORT
      LAYER metal4 ;
      RECT 0.00000 52.36000 0.21000 52.50000 ;
    END
  END rd_out[186]
  PIN rd_out[187]
    DIRECTION OUTPUT ;
    USE SIGNAL ;
    PORT
      LAYER metal4 ;
      RECT 0.00000 52.64000 0.21000 52.78000 ;
    END
  END rd_out[187]
  PIN rd_out[188]
    DIRECTION OUTPUT ;
    USE SIGNAL ;
    PORT
      LAYER metal4 ;
      RECT 0.00000 52.92000 0.21000 53.06000 ;
    END
  END rd_out[188]
  PIN rd_out[189]
    DIRECTION OUTPUT ;
    USE SIGNAL ;
    PORT
      LAYER metal4 ;
      RECT 0.00000 53.20000 0.21000 53.34000 ;
    END
  END rd_out[189]
  PIN rd_out[190]
    DIRECTION OUTPUT ;
    USE SIGNAL ;
    PORT
      LAYER metal4 ;
      RECT 0.00000 53.48000 0.21000 53.62000 ;
    END
  END rd_out[190]
  PIN rd_out[191]
    DIRECTION OUTPUT ;
    USE SIGNAL ;
    PORT
      LAYER metal4 ;
      RECT 0.00000 53.76000 0.21000 53.90000 ;
    END
  END rd_out[191]
  PIN rd_out[192]
    DIRECTION OUTPUT ;
    USE SIGNAL ;
    PORT
      LAYER metal4 ;
      RECT 0.00000 54.04000 0.21000 54.18000 ;
    END
  END rd_out[192]
  PIN rd_out[193]
    DIRECTION OUTPUT ;
    USE SIGNAL ;
    PORT
      LAYER metal4 ;
      RECT 0.00000 54.32000 0.21000 54.46000 ;
    END
  END rd_out[193]
  PIN rd_out[194]
    DIRECTION OUTPUT ;
    USE SIGNAL ;
    PORT
      LAYER metal4 ;
      RECT 0.00000 54.60000 0.21000 54.74000 ;
    END
  END rd_out[194]
  PIN rd_out[195]
    DIRECTION OUTPUT ;
    USE SIGNAL ;
    PORT
      LAYER metal4 ;
      RECT 0.00000 54.88000 0.21000 55.02000 ;
    END
  END rd_out[195]
  PIN rd_out[196]
    DIRECTION OUTPUT ;
    USE SIGNAL ;
    PORT
      LAYER metal4 ;
      RECT 0.00000 55.16000 0.21000 55.30000 ;
    END
  END rd_out[196]
  PIN rd_out[197]
    DIRECTION OUTPUT ;
    USE SIGNAL ;
    PORT
      LAYER metal4 ;
      RECT 0.00000 55.44000 0.21000 55.58000 ;
    END
  END rd_out[197]
  PIN rd_out[198]
    DIRECTION OUTPUT ;
    USE SIGNAL ;
    PORT
      LAYER metal4 ;
      RECT 0.00000 55.72000 0.21000 55.86000 ;
    END
  END rd_out[198]
  PIN rd_out[199]
    DIRECTION OUTPUT ;
    USE SIGNAL ;
    PORT
      LAYER metal4 ;
      RECT 0.00000 56.00000 0.21000 56.14000 ;
    END
  END rd_out[199]
  PIN rd_out[200]
    DIRECTION OUTPUT ;
    USE SIGNAL ;
    PORT
      LAYER metal4 ;
      RECT 0.00000 56.28000 0.21000 56.42000 ;
    END
  END rd_out[200]
  PIN rd_out[201]
    DIRECTION OUTPUT ;
    USE SIGNAL ;
    PORT
      LAYER metal4 ;
      RECT 0.00000 56.56000 0.21000 56.70000 ;
    END
  END rd_out[201]
  PIN rd_out[202]
    DIRECTION OUTPUT ;
    USE SIGNAL ;
    PORT
      LAYER metal4 ;
      RECT 0.00000 56.84000 0.21000 56.98000 ;
    END
  END rd_out[202]
  PIN rd_out[203]
    DIRECTION OUTPUT ;
    USE SIGNAL ;
    PORT
      LAYER metal4 ;
      RECT 0.00000 57.12000 0.21000 57.26000 ;
    END
  END rd_out[203]
  PIN rd_out[204]
    DIRECTION OUTPUT ;
    USE SIGNAL ;
    PORT
      LAYER metal4 ;
      RECT 0.00000 57.40000 0.21000 57.54000 ;
    END
  END rd_out[204]
  PIN rd_out[205]
    DIRECTION OUTPUT ;
    USE SIGNAL ;
    PORT
      LAYER metal4 ;
      RECT 0.00000 57.68000 0.21000 57.82000 ;
    END
  END rd_out[205]
  PIN rd_out[206]
    DIRECTION OUTPUT ;
    USE SIGNAL ;
    PORT
      LAYER metal4 ;
      RECT 0.00000 57.96000 0.21000 58.10000 ;
    END
  END rd_out[206]
  PIN rd_out[207]
    DIRECTION OUTPUT ;
    USE SIGNAL ;
    PORT
      LAYER metal4 ;
      RECT 0.00000 58.24000 0.21000 58.38000 ;
    END
  END rd_out[207]
  PIN rd_out[208]
    DIRECTION OUTPUT ;
    USE SIGNAL ;
    PORT
      LAYER metal4 ;
      RECT 0.00000 58.52000 0.21000 58.66000 ;
    END
  END rd_out[208]
  PIN rd_out[209]
    DIRECTION OUTPUT ;
    USE SIGNAL ;
    PORT
      LAYER metal4 ;
      RECT 0.00000 58.80000 0.21000 58.94000 ;
    END
  END rd_out[209]
  PIN rd_out[210]
    DIRECTION OUTPUT ;
    USE SIGNAL ;
    PORT
      LAYER metal4 ;
      RECT 0.00000 59.08000 0.21000 59.22000 ;
    END
  END rd_out[210]
  PIN rd_out[211]
    DIRECTION OUTPUT ;
    USE SIGNAL ;
    PORT
      LAYER metal4 ;
      RECT 0.00000 59.36000 0.21000 59.50000 ;
    END
  END rd_out[211]
  PIN rd_out[212]
    DIRECTION OUTPUT ;
    USE SIGNAL ;
    PORT
      LAYER metal4 ;
      RECT 0.00000 59.64000 0.21000 59.78000 ;
    END
  END rd_out[212]
  PIN rd_out[213]
    DIRECTION OUTPUT ;
    USE SIGNAL ;
    PORT
      LAYER metal4 ;
      RECT 0.00000 59.92000 0.21000 60.06000 ;
    END
  END rd_out[213]
  PIN rd_out[214]
    DIRECTION OUTPUT ;
    USE SIGNAL ;
    PORT
      LAYER metal4 ;
      RECT 0.00000 60.20000 0.21000 60.34000 ;
    END
  END rd_out[214]
  PIN rd_out[215]
    DIRECTION OUTPUT ;
    USE SIGNAL ;
    PORT
      LAYER metal4 ;
      RECT 0.00000 60.48000 0.21000 60.62000 ;
    END
  END rd_out[215]
  PIN rd_out[216]
    DIRECTION OUTPUT ;
    USE SIGNAL ;
    PORT
      LAYER metal4 ;
      RECT 0.00000 60.76000 0.21000 60.90000 ;
    END
  END rd_out[216]
  PIN rd_out[217]
    DIRECTION OUTPUT ;
    USE SIGNAL ;
    PORT
      LAYER metal4 ;
      RECT 0.00000 61.04000 0.21000 61.18000 ;
    END
  END rd_out[217]
  PIN rd_out[218]
    DIRECTION OUTPUT ;
    USE SIGNAL ;
    PORT
      LAYER metal4 ;
      RECT 0.00000 61.32000 0.21000 61.46000 ;
    END
  END rd_out[218]
  PIN rd_out[219]
    DIRECTION OUTPUT ;
    USE SIGNAL ;
    PORT
      LAYER metal4 ;
      RECT 0.00000 61.60000 0.21000 61.74000 ;
    END
  END rd_out[219]
  PIN rd_out[220]
    DIRECTION OUTPUT ;
    USE SIGNAL ;
    PORT
      LAYER metal4 ;
      RECT 0.00000 61.88000 0.21000 62.02000 ;
    END
  END rd_out[220]
  PIN rd_out[221]
    DIRECTION OUTPUT ;
    USE SIGNAL ;
    PORT
      LAYER metal4 ;
      RECT 0.00000 62.16000 0.21000 62.30000 ;
    END
  END rd_out[221]
  PIN rd_out[222]
    DIRECTION OUTPUT ;
    USE SIGNAL ;
    PORT
      LAYER metal4 ;
      RECT 0.00000 62.44000 0.21000 62.58000 ;
    END
  END rd_out[222]
  PIN rd_out[223]
    DIRECTION OUTPUT ;
    USE SIGNAL ;
    PORT
      LAYER metal4 ;
      RECT 0.00000 62.72000 0.21000 62.86000 ;
    END
  END rd_out[223]
  PIN rd_out[224]
    DIRECTION OUTPUT ;
    USE SIGNAL ;
    PORT
      LAYER metal4 ;
      RECT 0.00000 63.00000 0.21000 63.14000 ;
    END
  END rd_out[224]
  PIN rd_out[225]
    DIRECTION OUTPUT ;
    USE SIGNAL ;
    PORT
      LAYER metal4 ;
      RECT 0.00000 63.28000 0.21000 63.42000 ;
    END
  END rd_out[225]
  PIN rd_out[226]
    DIRECTION OUTPUT ;
    USE SIGNAL ;
    PORT
      LAYER metal4 ;
      RECT 0.00000 63.56000 0.21000 63.70000 ;
    END
  END rd_out[226]
  PIN rd_out[227]
    DIRECTION OUTPUT ;
    USE SIGNAL ;
    PORT
      LAYER metal4 ;
      RECT 0.00000 63.84000 0.21000 63.98000 ;
    END
  END rd_out[227]
  PIN rd_out[228]
    DIRECTION OUTPUT ;
    USE SIGNAL ;
    PORT
      LAYER metal4 ;
      RECT 0.00000 64.12000 0.21000 64.26000 ;
    END
  END rd_out[228]
  PIN rd_out[229]
    DIRECTION OUTPUT ;
    USE SIGNAL ;
    PORT
      LAYER metal4 ;
      RECT 0.00000 64.40000 0.21000 64.54000 ;
    END
  END rd_out[229]
  PIN rd_out[230]
    DIRECTION OUTPUT ;
    USE SIGNAL ;
    PORT
      LAYER metal4 ;
      RECT 0.00000 64.68000 0.21000 64.82000 ;
    END
  END rd_out[230]
  PIN rd_out[231]
    DIRECTION OUTPUT ;
    USE SIGNAL ;
    PORT
      LAYER metal4 ;
      RECT 0.00000 64.96000 0.21000 65.10000 ;
    END
  END rd_out[231]
  PIN rd_out[232]
    DIRECTION OUTPUT ;
    USE SIGNAL ;
    PORT
      LAYER metal4 ;
      RECT 0.00000 65.24000 0.21000 65.38000 ;
    END
  END rd_out[232]
  PIN rd_out[233]
    DIRECTION OUTPUT ;
    USE SIGNAL ;
    PORT
      LAYER metal4 ;
      RECT 0.00000 65.52000 0.21000 65.66000 ;
    END
  END rd_out[233]
  PIN rd_out[234]
    DIRECTION OUTPUT ;
    USE SIGNAL ;
    PORT
      LAYER metal4 ;
      RECT 0.00000 65.80000 0.21000 65.94000 ;
    END
  END rd_out[234]
  PIN rd_out[235]
    DIRECTION OUTPUT ;
    USE SIGNAL ;
    PORT
      LAYER metal4 ;
      RECT 0.00000 66.08000 0.21000 66.22000 ;
    END
  END rd_out[235]
  PIN rd_out[236]
    DIRECTION OUTPUT ;
    USE SIGNAL ;
    PORT
      LAYER metal4 ;
      RECT 0.00000 66.36000 0.21000 66.50000 ;
    END
  END rd_out[236]
  PIN rd_out[237]
    DIRECTION OUTPUT ;
    USE SIGNAL ;
    PORT
      LAYER metal4 ;
      RECT 0.00000 66.64000 0.21000 66.78000 ;
    END
  END rd_out[237]
  PIN rd_out[238]
    DIRECTION OUTPUT ;
    USE SIGNAL ;
    PORT
      LAYER metal4 ;
      RECT 0.00000 66.92000 0.21000 67.06000 ;
    END
  END rd_out[238]
  PIN rd_out[239]
    DIRECTION OUTPUT ;
    USE SIGNAL ;
    PORT
      LAYER metal4 ;
      RECT 0.00000 67.20000 0.21000 67.34000 ;
    END
  END rd_out[239]
  PIN rd_out[240]
    DIRECTION OUTPUT ;
    USE SIGNAL ;
    PORT
      LAYER metal4 ;
      RECT 0.00000 67.48000 0.21000 67.62000 ;
    END
  END rd_out[240]
  PIN rd_out[241]
    DIRECTION OUTPUT ;
    USE SIGNAL ;
    PORT
      LAYER metal4 ;
      RECT 0.00000 67.76000 0.21000 67.90000 ;
    END
  END rd_out[241]
  PIN rd_out[242]
    DIRECTION OUTPUT ;
    USE SIGNAL ;
    PORT
      LAYER metal4 ;
      RECT 0.00000 68.04000 0.21000 68.18000 ;
    END
  END rd_out[242]
  PIN rd_out[243]
    DIRECTION OUTPUT ;
    USE SIGNAL ;
    PORT
      LAYER metal4 ;
      RECT 0.00000 68.32000 0.21000 68.46000 ;
    END
  END rd_out[243]
  PIN rd_out[244]
    DIRECTION OUTPUT ;
    USE SIGNAL ;
    PORT
      LAYER metal4 ;
      RECT 0.00000 68.60000 0.21000 68.74000 ;
    END
  END rd_out[244]
  PIN rd_out[245]
    DIRECTION OUTPUT ;
    USE SIGNAL ;
    PORT
      LAYER metal4 ;
      RECT 0.00000 68.88000 0.21000 69.02000 ;
    END
  END rd_out[245]
  PIN rd_out[246]
    DIRECTION OUTPUT ;
    USE SIGNAL ;
    PORT
      LAYER metal4 ;
      RECT 0.00000 69.16000 0.21000 69.30000 ;
    END
  END rd_out[246]
  PIN rd_out[247]
    DIRECTION OUTPUT ;
    USE SIGNAL ;
    PORT
      LAYER metal4 ;
      RECT 0.00000 69.44000 0.21000 69.58000 ;
    END
  END rd_out[247]
  PIN rd_out[248]
    DIRECTION OUTPUT ;
    USE SIGNAL ;
    PORT
      LAYER metal4 ;
      RECT 0.00000 69.72000 0.21000 69.86000 ;
    END
  END rd_out[248]
  PIN rd_out[249]
    DIRECTION OUTPUT ;
    USE SIGNAL ;
    PORT
      LAYER metal4 ;
      RECT 0.00000 70.00000 0.21000 70.14000 ;
    END
  END rd_out[249]
  PIN rd_out[250]
    DIRECTION OUTPUT ;
    USE SIGNAL ;
    PORT
      LAYER metal4 ;
      RECT 0.00000 70.28000 0.21000 70.42000 ;
    END
  END rd_out[250]
  PIN rd_out[251]
    DIRECTION OUTPUT ;
    USE SIGNAL ;
    PORT
      LAYER metal4 ;
      RECT 0.00000 70.56000 0.21000 70.70000 ;
    END
  END rd_out[251]
  PIN rd_out[252]
    DIRECTION OUTPUT ;
    USE SIGNAL ;
    PORT
      LAYER metal4 ;
      RECT 0.00000 70.84000 0.21000 70.98000 ;
    END
  END rd_out[252]
  PIN rd_out[253]
    DIRECTION OUTPUT ;
    USE SIGNAL ;
    PORT
      LAYER metal4 ;
      RECT 0.00000 71.12000 0.21000 71.26000 ;
    END
  END rd_out[253]
  PIN rd_out[254]
    DIRECTION OUTPUT ;
    USE SIGNAL ;
    PORT
      LAYER metal4 ;
      RECT 0.00000 71.40000 0.21000 71.54000 ;
    END
  END rd_out[254]
  PIN rd_out[255]
    DIRECTION OUTPUT ;
    USE SIGNAL ;
    PORT
      LAYER metal4 ;
      RECT 0.00000 71.68000 0.21000 71.82000 ;
    END
  END rd_out[255]
  PIN wd_in[0]
    DIRECTION INPUT ;
    USE SIGNAL ;
    PORT
      LAYER metal4 ;
      RECT 0.00000 71.96000 0.21000 72.10000 ;
    END
  END wd_in[0]
  PIN wd_in[1]
    DIRECTION INPUT ;
    USE SIGNAL ;
    PORT
      LAYER metal4 ;
      RECT 0.00000 72.24000 0.21000 72.38000 ;
    END
  END wd_in[1]
  PIN wd_in[2]
    DIRECTION INPUT ;
    USE SIGNAL ;
    PORT
      LAYER metal4 ;
      RECT 0.00000 72.52000 0.21000 72.66000 ;
    END
  END wd_in[2]
  PIN wd_in[3]
    DIRECTION INPUT ;
    USE SIGNAL ;
    PORT
      LAYER metal4 ;
      RECT 0.00000 72.80000 0.21000 72.94000 ;
    END
  END wd_in[3]
  PIN wd_in[4]
    DIRECTION INPUT ;
    USE SIGNAL ;
    PORT
      LAYER metal4 ;
      RECT 0.00000 73.08000 0.21000 73.22000 ;
    END
  END wd_in[4]
  PIN wd_in[5]
    DIRECTION INPUT ;
    USE SIGNAL ;
    PORT
      LAYER metal4 ;
      RECT 0.00000 73.36000 0.21000 73.50000 ;
    END
  END wd_in[5]
  PIN wd_in[6]
    DIRECTION INPUT ;
    USE SIGNAL ;
    PORT
      LAYER metal4 ;
      RECT 0.00000 73.64000 0.21000 73.78000 ;
    END
  END wd_in[6]
  PIN wd_in[7]
    DIRECTION INPUT ;
    USE SIGNAL ;
    PORT
      LAYER metal4 ;
      RECT 0.00000 73.92000 0.21000 74.06000 ;
    END
  END wd_in[7]
  PIN wd_in[8]
    DIRECTION INPUT ;
    USE SIGNAL ;
    PORT
      LAYER metal4 ;
      RECT 0.00000 74.20000 0.21000 74.34000 ;
    END
  END wd_in[8]
  PIN wd_in[9]
    DIRECTION INPUT ;
    USE SIGNAL ;
    PORT
      LAYER metal4 ;
      RECT 0.00000 74.48000 0.21000 74.62000 ;
    END
  END wd_in[9]
  PIN wd_in[10]
    DIRECTION INPUT ;
    USE SIGNAL ;
    PORT
      LAYER metal4 ;
      RECT 0.00000 74.76000 0.21000 74.90000 ;
    END
  END wd_in[10]
  PIN wd_in[11]
    DIRECTION INPUT ;
    USE SIGNAL ;
    PORT
      LAYER metal4 ;
      RECT 0.00000 75.04000 0.21000 75.18000 ;
    END
  END wd_in[11]
  PIN wd_in[12]
    DIRECTION INPUT ;
    USE SIGNAL ;
    PORT
      LAYER metal4 ;
      RECT 0.00000 75.32000 0.21000 75.46000 ;
    END
  END wd_in[12]
  PIN wd_in[13]
    DIRECTION INPUT ;
    USE SIGNAL ;
    PORT
      LAYER metal4 ;
      RECT 0.00000 75.60000 0.21000 75.74000 ;
    END
  END wd_in[13]
  PIN wd_in[14]
    DIRECTION INPUT ;
    USE SIGNAL ;
    PORT
      LAYER metal4 ;
      RECT 0.00000 75.88000 0.21000 76.02000 ;
    END
  END wd_in[14]
  PIN wd_in[15]
    DIRECTION INPUT ;
    USE SIGNAL ;
    PORT
      LAYER metal4 ;
      RECT 0.00000 76.16000 0.21000 76.30000 ;
    END
  END wd_in[15]
  PIN wd_in[16]
    DIRECTION INPUT ;
    USE SIGNAL ;
    PORT
      LAYER metal4 ;
      RECT 0.00000 76.44000 0.21000 76.58000 ;
    END
  END wd_in[16]
  PIN wd_in[17]
    DIRECTION INPUT ;
    USE SIGNAL ;
    PORT
      LAYER metal4 ;
      RECT 0.00000 76.72000 0.21000 76.86000 ;
    END
  END wd_in[17]
  PIN wd_in[18]
    DIRECTION INPUT ;
    USE SIGNAL ;
    PORT
      LAYER metal4 ;
      RECT 0.00000 77.00000 0.21000 77.14000 ;
    END
  END wd_in[18]
  PIN wd_in[19]
    DIRECTION INPUT ;
    USE SIGNAL ;
    PORT
      LAYER metal4 ;
      RECT 0.00000 77.28000 0.21000 77.42000 ;
    END
  END wd_in[19]
  PIN wd_in[20]
    DIRECTION INPUT ;
    USE SIGNAL ;
    PORT
      LAYER metal4 ;
      RECT 0.00000 77.56000 0.21000 77.70000 ;
    END
  END wd_in[20]
  PIN wd_in[21]
    DIRECTION INPUT ;
    USE SIGNAL ;
    PORT
      LAYER metal4 ;
      RECT 0.00000 77.84000 0.21000 77.98000 ;
    END
  END wd_in[21]
  PIN wd_in[22]
    DIRECTION INPUT ;
    USE SIGNAL ;
    PORT
      LAYER metal4 ;
      RECT 0.00000 78.12000 0.21000 78.26000 ;
    END
  END wd_in[22]
  PIN wd_in[23]
    DIRECTION INPUT ;
    USE SIGNAL ;
    PORT
      LAYER metal4 ;
      RECT 0.00000 78.40000 0.21000 78.54000 ;
    END
  END wd_in[23]
  PIN wd_in[24]
    DIRECTION INPUT ;
    USE SIGNAL ;
    PORT
      LAYER metal4 ;
      RECT 0.00000 78.68000 0.21000 78.82000 ;
    END
  END wd_in[24]
  PIN wd_in[25]
    DIRECTION INPUT ;
    USE SIGNAL ;
    PORT
      LAYER metal4 ;
      RECT 0.00000 78.96000 0.21000 79.10000 ;
    END
  END wd_in[25]
  PIN wd_in[26]
    DIRECTION INPUT ;
    USE SIGNAL ;
    PORT
      LAYER metal4 ;
      RECT 0.00000 79.24000 0.21000 79.38000 ;
    END
  END wd_in[26]
  PIN wd_in[27]
    DIRECTION INPUT ;
    USE SIGNAL ;
    PORT
      LAYER metal4 ;
      RECT 0.00000 79.52000 0.21000 79.66000 ;
    END
  END wd_in[27]
  PIN wd_in[28]
    DIRECTION INPUT ;
    USE SIGNAL ;
    PORT
      LAYER metal4 ;
      RECT 0.00000 79.80000 0.21000 79.94000 ;
    END
  END wd_in[28]
  PIN wd_in[29]
    DIRECTION INPUT ;
    USE SIGNAL ;
    PORT
      LAYER metal4 ;
      RECT 0.00000 80.08000 0.21000 80.22000 ;
    END
  END wd_in[29]
  PIN wd_in[30]
    DIRECTION INPUT ;
    USE SIGNAL ;
    PORT
      LAYER metal4 ;
      RECT 0.00000 80.36000 0.21000 80.50000 ;
    END
  END wd_in[30]
  PIN wd_in[31]
    DIRECTION INPUT ;
    USE SIGNAL ;
    PORT
      LAYER metal4 ;
      RECT 0.00000 80.64000 0.21000 80.78000 ;
    END
  END wd_in[31]
  PIN wd_in[32]
    DIRECTION INPUT ;
    USE SIGNAL ;
    PORT
      LAYER metal4 ;
      RECT 0.00000 80.92000 0.21000 81.06000 ;
    END
  END wd_in[32]
  PIN wd_in[33]
    DIRECTION INPUT ;
    USE SIGNAL ;
    PORT
      LAYER metal4 ;
      RECT 0.00000 81.20000 0.21000 81.34000 ;
    END
  END wd_in[33]
  PIN wd_in[34]
    DIRECTION INPUT ;
    USE SIGNAL ;
    PORT
      LAYER metal4 ;
      RECT 0.00000 81.48000 0.21000 81.62000 ;
    END
  END wd_in[34]
  PIN wd_in[35]
    DIRECTION INPUT ;
    USE SIGNAL ;
    PORT
      LAYER metal4 ;
      RECT 0.00000 81.76000 0.21000 81.90000 ;
    END
  END wd_in[35]
  PIN wd_in[36]
    DIRECTION INPUT ;
    USE SIGNAL ;
    PORT
      LAYER metal4 ;
      RECT 0.00000 82.04000 0.21000 82.18000 ;
    END
  END wd_in[36]
  PIN wd_in[37]
    DIRECTION INPUT ;
    USE SIGNAL ;
    PORT
      LAYER metal4 ;
      RECT 0.00000 82.32000 0.21000 82.46000 ;
    END
  END wd_in[37]
  PIN wd_in[38]
    DIRECTION INPUT ;
    USE SIGNAL ;
    PORT
      LAYER metal4 ;
      RECT 0.00000 82.60000 0.21000 82.74000 ;
    END
  END wd_in[38]
  PIN wd_in[39]
    DIRECTION INPUT ;
    USE SIGNAL ;
    PORT
      LAYER metal4 ;
      RECT 0.00000 82.88000 0.21000 83.02000 ;
    END
  END wd_in[39]
  PIN wd_in[40]
    DIRECTION INPUT ;
    USE SIGNAL ;
    PORT
      LAYER metal4 ;
      RECT 0.00000 83.16000 0.21000 83.30000 ;
    END
  END wd_in[40]
  PIN wd_in[41]
    DIRECTION INPUT ;
    USE SIGNAL ;
    PORT
      LAYER metal4 ;
      RECT 0.00000 83.44000 0.21000 83.58000 ;
    END
  END wd_in[41]
  PIN wd_in[42]
    DIRECTION INPUT ;
    USE SIGNAL ;
    PORT
      LAYER metal4 ;
      RECT 0.00000 83.72000 0.21000 83.86000 ;
    END
  END wd_in[42]
  PIN wd_in[43]
    DIRECTION INPUT ;
    USE SIGNAL ;
    PORT
      LAYER metal4 ;
      RECT 0.00000 84.00000 0.21000 84.14000 ;
    END
  END wd_in[43]
  PIN wd_in[44]
    DIRECTION INPUT ;
    USE SIGNAL ;
    PORT
      LAYER metal4 ;
      RECT 0.00000 84.28000 0.21000 84.42000 ;
    END
  END wd_in[44]
  PIN wd_in[45]
    DIRECTION INPUT ;
    USE SIGNAL ;
    PORT
      LAYER metal4 ;
      RECT 0.00000 84.56000 0.21000 84.70000 ;
    END
  END wd_in[45]
  PIN wd_in[46]
    DIRECTION INPUT ;
    USE SIGNAL ;
    PORT
      LAYER metal4 ;
      RECT 0.00000 84.84000 0.21000 84.98000 ;
    END
  END wd_in[46]
  PIN wd_in[47]
    DIRECTION INPUT ;
    USE SIGNAL ;
    PORT
      LAYER metal4 ;
      RECT 0.00000 85.12000 0.21000 85.26000 ;
    END
  END wd_in[47]
  PIN wd_in[48]
    DIRECTION INPUT ;
    USE SIGNAL ;
    PORT
      LAYER metal4 ;
      RECT 0.00000 85.40000 0.21000 85.54000 ;
    END
  END wd_in[48]
  PIN wd_in[49]
    DIRECTION INPUT ;
    USE SIGNAL ;
    PORT
      LAYER metal4 ;
      RECT 0.00000 85.68000 0.21000 85.82000 ;
    END
  END wd_in[49]
  PIN wd_in[50]
    DIRECTION INPUT ;
    USE SIGNAL ;
    PORT
      LAYER metal4 ;
      RECT 0.00000 85.96000 0.21000 86.10000 ;
    END
  END wd_in[50]
  PIN wd_in[51]
    DIRECTION INPUT ;
    USE SIGNAL ;
    PORT
      LAYER metal4 ;
      RECT 0.00000 86.24000 0.21000 86.38000 ;
    END
  END wd_in[51]
  PIN wd_in[52]
    DIRECTION INPUT ;
    USE SIGNAL ;
    PORT
      LAYER metal4 ;
      RECT 0.00000 86.52000 0.21000 86.66000 ;
    END
  END wd_in[52]
  PIN wd_in[53]
    DIRECTION INPUT ;
    USE SIGNAL ;
    PORT
      LAYER metal4 ;
      RECT 0.00000 86.80000 0.21000 86.94000 ;
    END
  END wd_in[53]
  PIN wd_in[54]
    DIRECTION INPUT ;
    USE SIGNAL ;
    PORT
      LAYER metal4 ;
      RECT 0.00000 87.08000 0.21000 87.22000 ;
    END
  END wd_in[54]
  PIN wd_in[55]
    DIRECTION INPUT ;
    USE SIGNAL ;
    PORT
      LAYER metal4 ;
      RECT 0.00000 87.36000 0.21000 87.50000 ;
    END
  END wd_in[55]
  PIN wd_in[56]
    DIRECTION INPUT ;
    USE SIGNAL ;
    PORT
      LAYER metal4 ;
      RECT 0.00000 87.64000 0.21000 87.78000 ;
    END
  END wd_in[56]
  PIN wd_in[57]
    DIRECTION INPUT ;
    USE SIGNAL ;
    PORT
      LAYER metal4 ;
      RECT 0.00000 87.92000 0.21000 88.06000 ;
    END
  END wd_in[57]
  PIN wd_in[58]
    DIRECTION INPUT ;
    USE SIGNAL ;
    PORT
      LAYER metal4 ;
      RECT 0.00000 88.20000 0.21000 88.34000 ;
    END
  END wd_in[58]
  PIN wd_in[59]
    DIRECTION INPUT ;
    USE SIGNAL ;
    PORT
      LAYER metal4 ;
      RECT 0.00000 88.48000 0.21000 88.62000 ;
    END
  END wd_in[59]
  PIN wd_in[60]
    DIRECTION INPUT ;
    USE SIGNAL ;
    PORT
      LAYER metal4 ;
      RECT 0.00000 88.76000 0.21000 88.90000 ;
    END
  END wd_in[60]
  PIN wd_in[61]
    DIRECTION INPUT ;
    USE SIGNAL ;
    PORT
      LAYER metal4 ;
      RECT 0.00000 89.04000 0.21000 89.18000 ;
    END
  END wd_in[61]
  PIN wd_in[62]
    DIRECTION INPUT ;
    USE SIGNAL ;
    PORT
      LAYER metal4 ;
      RECT 0.00000 89.32000 0.21000 89.46000 ;
    END
  END wd_in[62]
  PIN wd_in[63]
    DIRECTION INPUT ;
    USE SIGNAL ;
    PORT
      LAYER metal4 ;
      RECT 0.00000 89.60000 0.21000 89.74000 ;
    END
  END wd_in[63]
  PIN wd_in[64]
    DIRECTION INPUT ;
    USE SIGNAL ;
    PORT
      LAYER metal4 ;
      RECT 0.00000 89.88000 0.21000 90.02000 ;
    END
  END wd_in[64]
  PIN wd_in[65]
    DIRECTION INPUT ;
    USE SIGNAL ;
    PORT
      LAYER metal4 ;
      RECT 0.00000 90.16000 0.21000 90.30000 ;
    END
  END wd_in[65]
  PIN wd_in[66]
    DIRECTION INPUT ;
    USE SIGNAL ;
    PORT
      LAYER metal4 ;
      RECT 0.00000 90.44000 0.21000 90.58000 ;
    END
  END wd_in[66]
  PIN wd_in[67]
    DIRECTION INPUT ;
    USE SIGNAL ;
    PORT
      LAYER metal4 ;
      RECT 0.00000 90.72000 0.21000 90.86000 ;
    END
  END wd_in[67]
  PIN wd_in[68]
    DIRECTION INPUT ;
    USE SIGNAL ;
    PORT
      LAYER metal4 ;
      RECT 0.00000 91.00000 0.21000 91.14000 ;
    END
  END wd_in[68]
  PIN wd_in[69]
    DIRECTION INPUT ;
    USE SIGNAL ;
    PORT
      LAYER metal4 ;
      RECT 0.00000 91.28000 0.21000 91.42000 ;
    END
  END wd_in[69]
  PIN wd_in[70]
    DIRECTION INPUT ;
    USE SIGNAL ;
    PORT
      LAYER metal4 ;
      RECT 0.00000 91.56000 0.21000 91.70000 ;
    END
  END wd_in[70]
  PIN wd_in[71]
    DIRECTION INPUT ;
    USE SIGNAL ;
    PORT
      LAYER metal4 ;
      RECT 0.00000 91.84000 0.21000 91.98000 ;
    END
  END wd_in[71]
  PIN wd_in[72]
    DIRECTION INPUT ;
    USE SIGNAL ;
    PORT
      LAYER metal4 ;
      RECT 0.00000 92.12000 0.21000 92.26000 ;
    END
  END wd_in[72]
  PIN wd_in[73]
    DIRECTION INPUT ;
    USE SIGNAL ;
    PORT
      LAYER metal4 ;
      RECT 0.00000 92.40000 0.21000 92.54000 ;
    END
  END wd_in[73]
  PIN wd_in[74]
    DIRECTION INPUT ;
    USE SIGNAL ;
    PORT
      LAYER metal4 ;
      RECT 0.00000 92.68000 0.21000 92.82000 ;
    END
  END wd_in[74]
  PIN wd_in[75]
    DIRECTION INPUT ;
    USE SIGNAL ;
    PORT
      LAYER metal4 ;
      RECT 0.00000 92.96000 0.21000 93.10000 ;
    END
  END wd_in[75]
  PIN wd_in[76]
    DIRECTION INPUT ;
    USE SIGNAL ;
    PORT
      LAYER metal4 ;
      RECT 0.00000 93.24000 0.21000 93.38000 ;
    END
  END wd_in[76]
  PIN wd_in[77]
    DIRECTION INPUT ;
    USE SIGNAL ;
    PORT
      LAYER metal4 ;
      RECT 0.00000 93.52000 0.21000 93.66000 ;
    END
  END wd_in[77]
  PIN wd_in[78]
    DIRECTION INPUT ;
    USE SIGNAL ;
    PORT
      LAYER metal4 ;
      RECT 0.00000 93.80000 0.21000 93.94000 ;
    END
  END wd_in[78]
  PIN wd_in[79]
    DIRECTION INPUT ;
    USE SIGNAL ;
    PORT
      LAYER metal4 ;
      RECT 0.00000 94.08000 0.21000 94.22000 ;
    END
  END wd_in[79]
  PIN wd_in[80]
    DIRECTION INPUT ;
    USE SIGNAL ;
    PORT
      LAYER metal4 ;
      RECT 0.00000 94.36000 0.21000 94.50000 ;
    END
  END wd_in[80]
  PIN wd_in[81]
    DIRECTION INPUT ;
    USE SIGNAL ;
    PORT
      LAYER metal4 ;
      RECT 0.00000 94.64000 0.21000 94.78000 ;
    END
  END wd_in[81]
  PIN wd_in[82]
    DIRECTION INPUT ;
    USE SIGNAL ;
    PORT
      LAYER metal4 ;
      RECT 0.00000 94.92000 0.21000 95.06000 ;
    END
  END wd_in[82]
  PIN wd_in[83]
    DIRECTION INPUT ;
    USE SIGNAL ;
    PORT
      LAYER metal4 ;
      RECT 0.00000 95.20000 0.21000 95.34000 ;
    END
  END wd_in[83]
  PIN wd_in[84]
    DIRECTION INPUT ;
    USE SIGNAL ;
    PORT
      LAYER metal4 ;
      RECT 0.00000 95.48000 0.21000 95.62000 ;
    END
  END wd_in[84]
  PIN wd_in[85]
    DIRECTION INPUT ;
    USE SIGNAL ;
    PORT
      LAYER metal4 ;
      RECT 0.00000 95.76000 0.21000 95.90000 ;
    END
  END wd_in[85]
  PIN wd_in[86]
    DIRECTION INPUT ;
    USE SIGNAL ;
    PORT
      LAYER metal4 ;
      RECT 0.00000 96.04000 0.21000 96.18000 ;
    END
  END wd_in[86]
  PIN wd_in[87]
    DIRECTION INPUT ;
    USE SIGNAL ;
    PORT
      LAYER metal4 ;
      RECT 0.00000 96.32000 0.21000 96.46000 ;
    END
  END wd_in[87]
  PIN wd_in[88]
    DIRECTION INPUT ;
    USE SIGNAL ;
    PORT
      LAYER metal4 ;
      RECT 0.00000 96.60000 0.21000 96.74000 ;
    END
  END wd_in[88]
  PIN wd_in[89]
    DIRECTION INPUT ;
    USE SIGNAL ;
    PORT
      LAYER metal4 ;
      RECT 0.00000 96.88000 0.21000 97.02000 ;
    END
  END wd_in[89]
  PIN wd_in[90]
    DIRECTION INPUT ;
    USE SIGNAL ;
    PORT
      LAYER metal4 ;
      RECT 0.00000 97.16000 0.21000 97.30000 ;
    END
  END wd_in[90]
  PIN wd_in[91]
    DIRECTION INPUT ;
    USE SIGNAL ;
    PORT
      LAYER metal4 ;
      RECT 0.00000 97.44000 0.21000 97.58000 ;
    END
  END wd_in[91]
  PIN wd_in[92]
    DIRECTION INPUT ;
    USE SIGNAL ;
    PORT
      LAYER metal4 ;
      RECT 0.00000 97.72000 0.21000 97.86000 ;
    END
  END wd_in[92]
  PIN wd_in[93]
    DIRECTION INPUT ;
    USE SIGNAL ;
    PORT
      LAYER metal4 ;
      RECT 0.00000 98.00000 0.21000 98.14000 ;
    END
  END wd_in[93]
  PIN wd_in[94]
    DIRECTION INPUT ;
    USE SIGNAL ;
    PORT
      LAYER metal4 ;
      RECT 0.00000 98.28000 0.21000 98.42000 ;
    END
  END wd_in[94]
  PIN wd_in[95]
    DIRECTION INPUT ;
    USE SIGNAL ;
    PORT
      LAYER metal4 ;
      RECT 0.00000 98.56000 0.21000 98.70000 ;
    END
  END wd_in[95]
  PIN wd_in[96]
    DIRECTION INPUT ;
    USE SIGNAL ;
    PORT
      LAYER metal4 ;
      RECT 0.00000 98.84000 0.21000 98.98000 ;
    END
  END wd_in[96]
  PIN wd_in[97]
    DIRECTION INPUT ;
    USE SIGNAL ;
    PORT
      LAYER metal4 ;
      RECT 0.00000 99.12000 0.21000 99.26000 ;
    END
  END wd_in[97]
  PIN wd_in[98]
    DIRECTION INPUT ;
    USE SIGNAL ;
    PORT
      LAYER metal4 ;
      RECT 0.00000 99.40000 0.21000 99.54000 ;
    END
  END wd_in[98]
  PIN wd_in[99]
    DIRECTION INPUT ;
    USE SIGNAL ;
    PORT
      LAYER metal4 ;
      RECT 0.00000 99.68000 0.21000 99.82000 ;
    END
  END wd_in[99]
  PIN wd_in[100]
    DIRECTION INPUT ;
    USE SIGNAL ;
    PORT
      LAYER metal4 ;
      RECT 0.00000 99.96000 0.21000 100.10000 ;
    END
  END wd_in[100]
  PIN wd_in[101]
    DIRECTION INPUT ;
    USE SIGNAL ;
    PORT
      LAYER metal4 ;
      RECT 0.00000 100.24000 0.21000 100.38000 ;
    END
  END wd_in[101]
  PIN wd_in[102]
    DIRECTION INPUT ;
    USE SIGNAL ;
    PORT
      LAYER metal4 ;
      RECT 0.00000 100.52000 0.21000 100.66000 ;
    END
  END wd_in[102]
  PIN wd_in[103]
    DIRECTION INPUT ;
    USE SIGNAL ;
    PORT
      LAYER metal4 ;
      RECT 0.00000 100.80000 0.21000 100.94000 ;
    END
  END wd_in[103]
  PIN wd_in[104]
    DIRECTION INPUT ;
    USE SIGNAL ;
    PORT
      LAYER metal4 ;
      RECT 0.00000 101.08000 0.21000 101.22000 ;
    END
  END wd_in[104]
  PIN wd_in[105]
    DIRECTION INPUT ;
    USE SIGNAL ;
    PORT
      LAYER metal4 ;
      RECT 0.00000 101.36000 0.21000 101.50000 ;
    END
  END wd_in[105]
  PIN wd_in[106]
    DIRECTION INPUT ;
    USE SIGNAL ;
    PORT
      LAYER metal4 ;
      RECT 0.00000 101.64000 0.21000 101.78000 ;
    END
  END wd_in[106]
  PIN wd_in[107]
    DIRECTION INPUT ;
    USE SIGNAL ;
    PORT
      LAYER metal4 ;
      RECT 0.00000 101.92000 0.21000 102.06000 ;
    END
  END wd_in[107]
  PIN wd_in[108]
    DIRECTION INPUT ;
    USE SIGNAL ;
    PORT
      LAYER metal4 ;
      RECT 0.00000 102.20000 0.21000 102.34000 ;
    END
  END wd_in[108]
  PIN wd_in[109]
    DIRECTION INPUT ;
    USE SIGNAL ;
    PORT
      LAYER metal4 ;
      RECT 0.00000 102.48000 0.21000 102.62000 ;
    END
  END wd_in[109]
  PIN wd_in[110]
    DIRECTION INPUT ;
    USE SIGNAL ;
    PORT
      LAYER metal4 ;
      RECT 0.00000 102.76000 0.21000 102.90000 ;
    END
  END wd_in[110]
  PIN wd_in[111]
    DIRECTION INPUT ;
    USE SIGNAL ;
    PORT
      LAYER metal4 ;
      RECT 0.00000 103.04000 0.21000 103.18000 ;
    END
  END wd_in[111]
  PIN wd_in[112]
    DIRECTION INPUT ;
    USE SIGNAL ;
    PORT
      LAYER metal4 ;
      RECT 0.00000 103.32000 0.21000 103.46000 ;
    END
  END wd_in[112]
  PIN wd_in[113]
    DIRECTION INPUT ;
    USE SIGNAL ;
    PORT
      LAYER metal4 ;
      RECT 0.00000 103.60000 0.21000 103.74000 ;
    END
  END wd_in[113]
  PIN wd_in[114]
    DIRECTION INPUT ;
    USE SIGNAL ;
    PORT
      LAYER metal4 ;
      RECT 0.00000 103.88000 0.21000 104.02000 ;
    END
  END wd_in[114]
  PIN wd_in[115]
    DIRECTION INPUT ;
    USE SIGNAL ;
    PORT
      LAYER metal4 ;
      RECT 0.00000 104.16000 0.21000 104.30000 ;
    END
  END wd_in[115]
  PIN wd_in[116]
    DIRECTION INPUT ;
    USE SIGNAL ;
    PORT
      LAYER metal4 ;
      RECT 0.00000 104.44000 0.21000 104.58000 ;
    END
  END wd_in[116]
  PIN wd_in[117]
    DIRECTION INPUT ;
    USE SIGNAL ;
    PORT
      LAYER metal4 ;
      RECT 0.00000 104.72000 0.21000 104.86000 ;
    END
  END wd_in[117]
  PIN wd_in[118]
    DIRECTION INPUT ;
    USE SIGNAL ;
    PORT
      LAYER metal4 ;
      RECT 0.00000 105.00000 0.21000 105.14000 ;
    END
  END wd_in[118]
  PIN wd_in[119]
    DIRECTION INPUT ;
    USE SIGNAL ;
    PORT
      LAYER metal4 ;
      RECT 0.00000 105.28000 0.21000 105.42000 ;
    END
  END wd_in[119]
  PIN wd_in[120]
    DIRECTION INPUT ;
    USE SIGNAL ;
    PORT
      LAYER metal4 ;
      RECT 0.00000 105.56000 0.21000 105.70000 ;
    END
  END wd_in[120]
  PIN wd_in[121]
    DIRECTION INPUT ;
    USE SIGNAL ;
    PORT
      LAYER metal4 ;
      RECT 0.00000 105.84000 0.21000 105.98000 ;
    END
  END wd_in[121]
  PIN wd_in[122]
    DIRECTION INPUT ;
    USE SIGNAL ;
    PORT
      LAYER metal4 ;
      RECT 0.00000 106.12000 0.21000 106.26000 ;
    END
  END wd_in[122]
  PIN wd_in[123]
    DIRECTION INPUT ;
    USE SIGNAL ;
    PORT
      LAYER metal4 ;
      RECT 0.00000 106.40000 0.21000 106.54000 ;
    END
  END wd_in[123]
  PIN wd_in[124]
    DIRECTION INPUT ;
    USE SIGNAL ;
    PORT
      LAYER metal4 ;
      RECT 0.00000 106.68000 0.21000 106.82000 ;
    END
  END wd_in[124]
  PIN wd_in[125]
    DIRECTION INPUT ;
    USE SIGNAL ;
    PORT
      LAYER metal4 ;
      RECT 0.00000 106.96000 0.21000 107.10000 ;
    END
  END wd_in[125]
  PIN wd_in[126]
    DIRECTION INPUT ;
    USE SIGNAL ;
    PORT
      LAYER metal4 ;
      RECT 0.00000 107.24000 0.21000 107.38000 ;
    END
  END wd_in[126]
  PIN wd_in[127]
    DIRECTION INPUT ;
    USE SIGNAL ;
    PORT
      LAYER metal4 ;
      RECT 0.00000 107.52000 0.21000 107.66000 ;
    END
  END wd_in[127]
  PIN wd_in[128]
    DIRECTION INPUT ;
    USE SIGNAL ;
    PORT
      LAYER metal4 ;
      RECT 0.00000 107.80000 0.21000 107.94000 ;
    END
  END wd_in[128]
  PIN wd_in[129]
    DIRECTION INPUT ;
    USE SIGNAL ;
    PORT
      LAYER metal4 ;
      RECT 0.00000 108.08000 0.21000 108.22000 ;
    END
  END wd_in[129]
  PIN wd_in[130]
    DIRECTION INPUT ;
    USE SIGNAL ;
    PORT
      LAYER metal4 ;
      RECT 0.00000 108.36000 0.21000 108.50000 ;
    END
  END wd_in[130]
  PIN wd_in[131]
    DIRECTION INPUT ;
    USE SIGNAL ;
    PORT
      LAYER metal4 ;
      RECT 0.00000 108.64000 0.21000 108.78000 ;
    END
  END wd_in[131]
  PIN wd_in[132]
    DIRECTION INPUT ;
    USE SIGNAL ;
    PORT
      LAYER metal4 ;
      RECT 0.00000 108.92000 0.21000 109.06000 ;
    END
  END wd_in[132]
  PIN wd_in[133]
    DIRECTION INPUT ;
    USE SIGNAL ;
    PORT
      LAYER metal4 ;
      RECT 0.00000 109.20000 0.21000 109.34000 ;
    END
  END wd_in[133]
  PIN wd_in[134]
    DIRECTION INPUT ;
    USE SIGNAL ;
    PORT
      LAYER metal4 ;
      RECT 0.00000 109.48000 0.21000 109.62000 ;
    END
  END wd_in[134]
  PIN wd_in[135]
    DIRECTION INPUT ;
    USE SIGNAL ;
    PORT
      LAYER metal4 ;
      RECT 0.00000 109.76000 0.21000 109.90000 ;
    END
  END wd_in[135]
  PIN wd_in[136]
    DIRECTION INPUT ;
    USE SIGNAL ;
    PORT
      LAYER metal4 ;
      RECT 0.00000 110.04000 0.21000 110.18000 ;
    END
  END wd_in[136]
  PIN wd_in[137]
    DIRECTION INPUT ;
    USE SIGNAL ;
    PORT
      LAYER metal4 ;
      RECT 0.00000 110.32000 0.21000 110.46000 ;
    END
  END wd_in[137]
  PIN wd_in[138]
    DIRECTION INPUT ;
    USE SIGNAL ;
    PORT
      LAYER metal4 ;
      RECT 0.00000 110.60000 0.21000 110.74000 ;
    END
  END wd_in[138]
  PIN wd_in[139]
    DIRECTION INPUT ;
    USE SIGNAL ;
    PORT
      LAYER metal4 ;
      RECT 0.00000 110.88000 0.21000 111.02000 ;
    END
  END wd_in[139]
  PIN wd_in[140]
    DIRECTION INPUT ;
    USE SIGNAL ;
    PORT
      LAYER metal4 ;
      RECT 0.00000 111.16000 0.21000 111.30000 ;
    END
  END wd_in[140]
  PIN wd_in[141]
    DIRECTION INPUT ;
    USE SIGNAL ;
    PORT
      LAYER metal4 ;
      RECT 0.00000 111.44000 0.21000 111.58000 ;
    END
  END wd_in[141]
  PIN wd_in[142]
    DIRECTION INPUT ;
    USE SIGNAL ;
    PORT
      LAYER metal4 ;
      RECT 0.00000 111.72000 0.21000 111.86000 ;
    END
  END wd_in[142]
  PIN wd_in[143]
    DIRECTION INPUT ;
    USE SIGNAL ;
    PORT
      LAYER metal4 ;
      RECT 0.00000 112.00000 0.21000 112.14000 ;
    END
  END wd_in[143]
  PIN wd_in[144]
    DIRECTION INPUT ;
    USE SIGNAL ;
    PORT
      LAYER metal4 ;
      RECT 0.00000 112.28000 0.21000 112.42000 ;
    END
  END wd_in[144]
  PIN wd_in[145]
    DIRECTION INPUT ;
    USE SIGNAL ;
    PORT
      LAYER metal4 ;
      RECT 0.00000 112.56000 0.21000 112.70000 ;
    END
  END wd_in[145]
  PIN wd_in[146]
    DIRECTION INPUT ;
    USE SIGNAL ;
    PORT
      LAYER metal4 ;
      RECT 0.00000 112.84000 0.21000 112.98000 ;
    END
  END wd_in[146]
  PIN wd_in[147]
    DIRECTION INPUT ;
    USE SIGNAL ;
    PORT
      LAYER metal4 ;
      RECT 0.00000 113.12000 0.21000 113.26000 ;
    END
  END wd_in[147]
  PIN wd_in[148]
    DIRECTION INPUT ;
    USE SIGNAL ;
    PORT
      LAYER metal4 ;
      RECT 0.00000 113.40000 0.21000 113.54000 ;
    END
  END wd_in[148]
  PIN wd_in[149]
    DIRECTION INPUT ;
    USE SIGNAL ;
    PORT
      LAYER metal4 ;
      RECT 0.00000 113.68000 0.21000 113.82000 ;
    END
  END wd_in[149]
  PIN wd_in[150]
    DIRECTION INPUT ;
    USE SIGNAL ;
    PORT
      LAYER metal4 ;
      RECT 0.00000 113.96000 0.21000 114.10000 ;
    END
  END wd_in[150]
  PIN wd_in[151]
    DIRECTION INPUT ;
    USE SIGNAL ;
    PORT
      LAYER metal4 ;
      RECT 0.00000 114.24000 0.21000 114.38000 ;
    END
  END wd_in[151]
  PIN wd_in[152]
    DIRECTION INPUT ;
    USE SIGNAL ;
    PORT
      LAYER metal4 ;
      RECT 0.00000 114.52000 0.21000 114.66000 ;
    END
  END wd_in[152]
  PIN wd_in[153]
    DIRECTION INPUT ;
    USE SIGNAL ;
    PORT
      LAYER metal4 ;
      RECT 0.00000 114.80000 0.21000 114.94000 ;
    END
  END wd_in[153]
  PIN wd_in[154]
    DIRECTION INPUT ;
    USE SIGNAL ;
    PORT
      LAYER metal4 ;
      RECT 0.00000 115.08000 0.21000 115.22000 ;
    END
  END wd_in[154]
  PIN wd_in[155]
    DIRECTION INPUT ;
    USE SIGNAL ;
    PORT
      LAYER metal4 ;
      RECT 0.00000 115.36000 0.21000 115.50000 ;
    END
  END wd_in[155]
  PIN wd_in[156]
    DIRECTION INPUT ;
    USE SIGNAL ;
    PORT
      LAYER metal4 ;
      RECT 0.00000 115.64000 0.21000 115.78000 ;
    END
  END wd_in[156]
  PIN wd_in[157]
    DIRECTION INPUT ;
    USE SIGNAL ;
    PORT
      LAYER metal4 ;
      RECT 0.00000 115.92000 0.21000 116.06000 ;
    END
  END wd_in[157]
  PIN wd_in[158]
    DIRECTION INPUT ;
    USE SIGNAL ;
    PORT
      LAYER metal4 ;
      RECT 0.00000 116.20000 0.21000 116.34000 ;
    END
  END wd_in[158]
  PIN wd_in[159]
    DIRECTION INPUT ;
    USE SIGNAL ;
    PORT
      LAYER metal4 ;
      RECT 0.00000 116.48000 0.21000 116.62000 ;
    END
  END wd_in[159]
  PIN wd_in[160]
    DIRECTION INPUT ;
    USE SIGNAL ;
    PORT
      LAYER metal4 ;
      RECT 0.00000 116.76000 0.21000 116.90000 ;
    END
  END wd_in[160]
  PIN wd_in[161]
    DIRECTION INPUT ;
    USE SIGNAL ;
    PORT
      LAYER metal4 ;
      RECT 0.00000 117.04000 0.21000 117.18000 ;
    END
  END wd_in[161]
  PIN wd_in[162]
    DIRECTION INPUT ;
    USE SIGNAL ;
    PORT
      LAYER metal4 ;
      RECT 0.00000 117.32000 0.21000 117.46000 ;
    END
  END wd_in[162]
  PIN wd_in[163]
    DIRECTION INPUT ;
    USE SIGNAL ;
    PORT
      LAYER metal4 ;
      RECT 0.00000 117.60000 0.21000 117.74000 ;
    END
  END wd_in[163]
  PIN wd_in[164]
    DIRECTION INPUT ;
    USE SIGNAL ;
    PORT
      LAYER metal4 ;
      RECT 0.00000 117.88000 0.21000 118.02000 ;
    END
  END wd_in[164]
  PIN wd_in[165]
    DIRECTION INPUT ;
    USE SIGNAL ;
    PORT
      LAYER metal4 ;
      RECT 0.00000 118.16000 0.21000 118.30000 ;
    END
  END wd_in[165]
  PIN wd_in[166]
    DIRECTION INPUT ;
    USE SIGNAL ;
    PORT
      LAYER metal4 ;
      RECT 0.00000 118.44000 0.21000 118.58000 ;
    END
  END wd_in[166]
  PIN wd_in[167]
    DIRECTION INPUT ;
    USE SIGNAL ;
    PORT
      LAYER metal4 ;
      RECT 0.00000 118.72000 0.21000 118.86000 ;
    END
  END wd_in[167]
  PIN wd_in[168]
    DIRECTION INPUT ;
    USE SIGNAL ;
    PORT
      LAYER metal4 ;
      RECT 0.00000 119.00000 0.21000 119.14000 ;
    END
  END wd_in[168]
  PIN wd_in[169]
    DIRECTION INPUT ;
    USE SIGNAL ;
    PORT
      LAYER metal4 ;
      RECT 0.00000 119.28000 0.21000 119.42000 ;
    END
  END wd_in[169]
  PIN wd_in[170]
    DIRECTION INPUT ;
    USE SIGNAL ;
    PORT
      LAYER metal4 ;
      RECT 0.00000 119.56000 0.21000 119.70000 ;
    END
  END wd_in[170]
  PIN wd_in[171]
    DIRECTION INPUT ;
    USE SIGNAL ;
    PORT
      LAYER metal4 ;
      RECT 0.00000 119.84000 0.21000 119.98000 ;
    END
  END wd_in[171]
  PIN wd_in[172]
    DIRECTION INPUT ;
    USE SIGNAL ;
    PORT
      LAYER metal4 ;
      RECT 0.00000 120.12000 0.21000 120.26000 ;
    END
  END wd_in[172]
  PIN wd_in[173]
    DIRECTION INPUT ;
    USE SIGNAL ;
    PORT
      LAYER metal4 ;
      RECT 0.00000 120.40000 0.21000 120.54000 ;
    END
  END wd_in[173]
  PIN wd_in[174]
    DIRECTION INPUT ;
    USE SIGNAL ;
    PORT
      LAYER metal4 ;
      RECT 0.00000 120.68000 0.21000 120.82000 ;
    END
  END wd_in[174]
  PIN wd_in[175]
    DIRECTION INPUT ;
    USE SIGNAL ;
    PORT
      LAYER metal4 ;
      RECT 0.00000 120.96000 0.21000 121.10000 ;
    END
  END wd_in[175]
  PIN wd_in[176]
    DIRECTION INPUT ;
    USE SIGNAL ;
    PORT
      LAYER metal4 ;
      RECT 0.00000 121.24000 0.21000 121.38000 ;
    END
  END wd_in[176]
  PIN wd_in[177]
    DIRECTION INPUT ;
    USE SIGNAL ;
    PORT
      LAYER metal4 ;
      RECT 0.00000 121.52000 0.21000 121.66000 ;
    END
  END wd_in[177]
  PIN wd_in[178]
    DIRECTION INPUT ;
    USE SIGNAL ;
    PORT
      LAYER metal4 ;
      RECT 0.00000 121.80000 0.21000 121.94000 ;
    END
  END wd_in[178]
  PIN wd_in[179]
    DIRECTION INPUT ;
    USE SIGNAL ;
    PORT
      LAYER metal4 ;
      RECT 0.00000 122.08000 0.21000 122.22000 ;
    END
  END wd_in[179]
  PIN wd_in[180]
    DIRECTION INPUT ;
    USE SIGNAL ;
    PORT
      LAYER metal4 ;
      RECT 0.00000 122.36000 0.21000 122.50000 ;
    END
  END wd_in[180]
  PIN wd_in[181]
    DIRECTION INPUT ;
    USE SIGNAL ;
    PORT
      LAYER metal4 ;
      RECT 0.00000 122.64000 0.21000 122.78000 ;
    END
  END wd_in[181]
  PIN wd_in[182]
    DIRECTION INPUT ;
    USE SIGNAL ;
    PORT
      LAYER metal4 ;
      RECT 0.00000 122.92000 0.21000 123.06000 ;
    END
  END wd_in[182]
  PIN wd_in[183]
    DIRECTION INPUT ;
    USE SIGNAL ;
    PORT
      LAYER metal4 ;
      RECT 0.00000 123.20000 0.21000 123.34000 ;
    END
  END wd_in[183]
  PIN wd_in[184]
    DIRECTION INPUT ;
    USE SIGNAL ;
    PORT
      LAYER metal4 ;
      RECT 0.00000 123.48000 0.21000 123.62000 ;
    END
  END wd_in[184]
  PIN wd_in[185]
    DIRECTION INPUT ;
    USE SIGNAL ;
    PORT
      LAYER metal4 ;
      RECT 0.00000 123.76000 0.21000 123.90000 ;
    END
  END wd_in[185]
  PIN wd_in[186]
    DIRECTION INPUT ;
    USE SIGNAL ;
    PORT
      LAYER metal4 ;
      RECT 0.00000 124.04000 0.21000 124.18000 ;
    END
  END wd_in[186]
  PIN wd_in[187]
    DIRECTION INPUT ;
    USE SIGNAL ;
    PORT
      LAYER metal4 ;
      RECT 0.00000 124.32000 0.21000 124.46000 ;
    END
  END wd_in[187]
  PIN wd_in[188]
    DIRECTION INPUT ;
    USE SIGNAL ;
    PORT
      LAYER metal4 ;
      RECT 0.00000 124.60000 0.21000 124.74000 ;
    END
  END wd_in[188]
  PIN wd_in[189]
    DIRECTION INPUT ;
    USE SIGNAL ;
    PORT
      LAYER metal4 ;
      RECT 0.00000 124.88000 0.21000 125.02000 ;
    END
  END wd_in[189]
  PIN wd_in[190]
    DIRECTION INPUT ;
    USE SIGNAL ;
    PORT
      LAYER metal4 ;
      RECT 0.00000 125.16000 0.21000 125.30000 ;
    END
  END wd_in[190]
  PIN wd_in[191]
    DIRECTION INPUT ;
    USE SIGNAL ;
    PORT
      LAYER metal4 ;
      RECT 0.00000 125.44000 0.21000 125.58000 ;
    END
  END wd_in[191]
  PIN wd_in[192]
    DIRECTION INPUT ;
    USE SIGNAL ;
    PORT
      LAYER metal4 ;
      RECT 0.00000 125.72000 0.21000 125.86000 ;
    END
  END wd_in[192]
  PIN wd_in[193]
    DIRECTION INPUT ;
    USE SIGNAL ;
    PORT
      LAYER metal4 ;
      RECT 0.00000 126.00000 0.21000 126.14000 ;
    END
  END wd_in[193]
  PIN wd_in[194]
    DIRECTION INPUT ;
    USE SIGNAL ;
    PORT
      LAYER metal4 ;
      RECT 0.00000 126.28000 0.21000 126.42000 ;
    END
  END wd_in[194]
  PIN wd_in[195]
    DIRECTION INPUT ;
    USE SIGNAL ;
    PORT
      LAYER metal4 ;
      RECT 0.00000 126.56000 0.21000 126.70000 ;
    END
  END wd_in[195]
  PIN wd_in[196]
    DIRECTION INPUT ;
    USE SIGNAL ;
    PORT
      LAYER metal4 ;
      RECT 0.00000 126.84000 0.21000 126.98000 ;
    END
  END wd_in[196]
  PIN wd_in[197]
    DIRECTION INPUT ;
    USE SIGNAL ;
    PORT
      LAYER metal4 ;
      RECT 0.00000 127.12000 0.21000 127.26000 ;
    END
  END wd_in[197]
  PIN wd_in[198]
    DIRECTION INPUT ;
    USE SIGNAL ;
    PORT
      LAYER metal4 ;
      RECT 0.00000 127.40000 0.21000 127.54000 ;
    END
  END wd_in[198]
  PIN wd_in[199]
    DIRECTION INPUT ;
    USE SIGNAL ;
    PORT
      LAYER metal4 ;
      RECT 0.00000 127.68000 0.21000 127.82000 ;
    END
  END wd_in[199]
  PIN wd_in[200]
    DIRECTION INPUT ;
    USE SIGNAL ;
    PORT
      LAYER metal4 ;
      RECT 0.00000 127.96000 0.21000 128.10000 ;
    END
  END wd_in[200]
  PIN wd_in[201]
    DIRECTION INPUT ;
    USE SIGNAL ;
    PORT
      LAYER metal4 ;
      RECT 0.00000 128.24000 0.21000 128.38000 ;
    END
  END wd_in[201]
  PIN wd_in[202]
    DIRECTION INPUT ;
    USE SIGNAL ;
    PORT
      LAYER metal4 ;
      RECT 0.00000 128.52000 0.21000 128.66000 ;
    END
  END wd_in[202]
  PIN wd_in[203]
    DIRECTION INPUT ;
    USE SIGNAL ;
    PORT
      LAYER metal4 ;
      RECT 0.00000 128.80000 0.21000 128.94000 ;
    END
  END wd_in[203]
  PIN wd_in[204]
    DIRECTION INPUT ;
    USE SIGNAL ;
    PORT
      LAYER metal4 ;
      RECT 0.00000 129.08000 0.21000 129.22000 ;
    END
  END wd_in[204]
  PIN wd_in[205]
    DIRECTION INPUT ;
    USE SIGNAL ;
    PORT
      LAYER metal4 ;
      RECT 0.00000 129.36000 0.21000 129.50000 ;
    END
  END wd_in[205]
  PIN wd_in[206]
    DIRECTION INPUT ;
    USE SIGNAL ;
    PORT
      LAYER metal4 ;
      RECT 0.00000 129.64000 0.21000 129.78000 ;
    END
  END wd_in[206]
  PIN wd_in[207]
    DIRECTION INPUT ;
    USE SIGNAL ;
    PORT
      LAYER metal4 ;
      RECT 0.00000 129.92000 0.21000 130.06000 ;
    END
  END wd_in[207]
  PIN wd_in[208]
    DIRECTION INPUT ;
    USE SIGNAL ;
    PORT
      LAYER metal4 ;
      RECT 0.00000 130.20000 0.21000 130.34000 ;
    END
  END wd_in[208]
  PIN wd_in[209]
    DIRECTION INPUT ;
    USE SIGNAL ;
    PORT
      LAYER metal4 ;
      RECT 0.00000 130.48000 0.21000 130.62000 ;
    END
  END wd_in[209]
  PIN wd_in[210]
    DIRECTION INPUT ;
    USE SIGNAL ;
    PORT
      LAYER metal4 ;
      RECT 0.00000 130.76000 0.21000 130.90000 ;
    END
  END wd_in[210]
  PIN wd_in[211]
    DIRECTION INPUT ;
    USE SIGNAL ;
    PORT
      LAYER metal4 ;
      RECT 0.00000 131.04000 0.21000 131.18000 ;
    END
  END wd_in[211]
  PIN wd_in[212]
    DIRECTION INPUT ;
    USE SIGNAL ;
    PORT
      LAYER metal4 ;
      RECT 0.00000 131.32000 0.21000 131.46000 ;
    END
  END wd_in[212]
  PIN wd_in[213]
    DIRECTION INPUT ;
    USE SIGNAL ;
    PORT
      LAYER metal4 ;
      RECT 0.00000 131.60000 0.21000 131.74000 ;
    END
  END wd_in[213]
  PIN wd_in[214]
    DIRECTION INPUT ;
    USE SIGNAL ;
    PORT
      LAYER metal4 ;
      RECT 0.00000 131.88000 0.21000 132.02000 ;
    END
  END wd_in[214]
  PIN wd_in[215]
    DIRECTION INPUT ;
    USE SIGNAL ;
    PORT
      LAYER metal4 ;
      RECT 0.00000 132.16000 0.21000 132.30000 ;
    END
  END wd_in[215]
  PIN wd_in[216]
    DIRECTION INPUT ;
    USE SIGNAL ;
    PORT
      LAYER metal4 ;
      RECT 0.00000 132.44000 0.21000 132.58000 ;
    END
  END wd_in[216]
  PIN wd_in[217]
    DIRECTION INPUT ;
    USE SIGNAL ;
    PORT
      LAYER metal4 ;
      RECT 0.00000 132.72000 0.21000 132.86000 ;
    END
  END wd_in[217]
  PIN wd_in[218]
    DIRECTION INPUT ;
    USE SIGNAL ;
    PORT
      LAYER metal4 ;
      RECT 0.00000 133.00000 0.21000 133.14000 ;
    END
  END wd_in[218]
  PIN wd_in[219]
    DIRECTION INPUT ;
    USE SIGNAL ;
    PORT
      LAYER metal4 ;
      RECT 0.00000 133.28000 0.21000 133.42000 ;
    END
  END wd_in[219]
  PIN wd_in[220]
    DIRECTION INPUT ;
    USE SIGNAL ;
    PORT
      LAYER metal4 ;
      RECT 0.00000 133.56000 0.21000 133.70000 ;
    END
  END wd_in[220]
  PIN wd_in[221]
    DIRECTION INPUT ;
    USE SIGNAL ;
    PORT
      LAYER metal4 ;
      RECT 0.00000 133.84000 0.21000 133.98000 ;
    END
  END wd_in[221]
  PIN wd_in[222]
    DIRECTION INPUT ;
    USE SIGNAL ;
    PORT
      LAYER metal4 ;
      RECT 0.00000 134.12000 0.21000 134.26000 ;
    END
  END wd_in[222]
  PIN wd_in[223]
    DIRECTION INPUT ;
    USE SIGNAL ;
    PORT
      LAYER metal4 ;
      RECT 0.00000 134.40000 0.21000 134.54000 ;
    END
  END wd_in[223]
  PIN wd_in[224]
    DIRECTION INPUT ;
    USE SIGNAL ;
    PORT
      LAYER metal4 ;
      RECT 0.00000 134.68000 0.21000 134.82000 ;
    END
  END wd_in[224]
  PIN wd_in[225]
    DIRECTION INPUT ;
    USE SIGNAL ;
    PORT
      LAYER metal4 ;
      RECT 0.00000 134.96000 0.21000 135.10000 ;
    END
  END wd_in[225]
  PIN wd_in[226]
    DIRECTION INPUT ;
    USE SIGNAL ;
    PORT
      LAYER metal4 ;
      RECT 0.00000 135.24000 0.21000 135.38000 ;
    END
  END wd_in[226]
  PIN wd_in[227]
    DIRECTION INPUT ;
    USE SIGNAL ;
    PORT
      LAYER metal4 ;
      RECT 0.00000 135.52000 0.21000 135.66000 ;
    END
  END wd_in[227]
  PIN wd_in[228]
    DIRECTION INPUT ;
    USE SIGNAL ;
    PORT
      LAYER metal4 ;
      RECT 0.00000 135.80000 0.21000 135.94000 ;
    END
  END wd_in[228]
  PIN wd_in[229]
    DIRECTION INPUT ;
    USE SIGNAL ;
    PORT
      LAYER metal4 ;
      RECT 0.00000 136.08000 0.21000 136.22000 ;
    END
  END wd_in[229]
  PIN wd_in[230]
    DIRECTION INPUT ;
    USE SIGNAL ;
    PORT
      LAYER metal4 ;
      RECT 0.00000 136.36000 0.21000 136.50000 ;
    END
  END wd_in[230]
  PIN wd_in[231]
    DIRECTION INPUT ;
    USE SIGNAL ;
    PORT
      LAYER metal4 ;
      RECT 0.00000 136.64000 0.21000 136.78000 ;
    END
  END wd_in[231]
  PIN wd_in[232]
    DIRECTION INPUT ;
    USE SIGNAL ;
    PORT
      LAYER metal4 ;
      RECT 0.00000 136.92000 0.21000 137.06000 ;
    END
  END wd_in[232]
  PIN wd_in[233]
    DIRECTION INPUT ;
    USE SIGNAL ;
    PORT
      LAYER metal4 ;
      RECT 0.00000 137.20000 0.21000 137.34000 ;
    END
  END wd_in[233]
  PIN wd_in[234]
    DIRECTION INPUT ;
    USE SIGNAL ;
    PORT
      LAYER metal4 ;
      RECT 0.00000 137.48000 0.21000 137.62000 ;
    END
  END wd_in[234]
  PIN wd_in[235]
    DIRECTION INPUT ;
    USE SIGNAL ;
    PORT
      LAYER metal4 ;
      RECT 0.00000 137.76000 0.21000 137.90000 ;
    END
  END wd_in[235]
  PIN wd_in[236]
    DIRECTION INPUT ;
    USE SIGNAL ;
    PORT
      LAYER metal4 ;
      RECT 0.00000 138.04000 0.21000 138.18000 ;
    END
  END wd_in[236]
  PIN wd_in[237]
    DIRECTION INPUT ;
    USE SIGNAL ;
    PORT
      LAYER metal4 ;
      RECT 0.00000 138.32000 0.21000 138.46000 ;
    END
  END wd_in[237]
  PIN wd_in[238]
    DIRECTION INPUT ;
    USE SIGNAL ;
    PORT
      LAYER metal4 ;
      RECT 0.00000 138.60000 0.21000 138.74000 ;
    END
  END wd_in[238]
  PIN wd_in[239]
    DIRECTION INPUT ;
    USE SIGNAL ;
    PORT
      LAYER metal4 ;
      RECT 0.00000 138.88000 0.21000 139.02000 ;
    END
  END wd_in[239]
  PIN wd_in[240]
    DIRECTION INPUT ;
    USE SIGNAL ;
    PORT
      LAYER metal4 ;
      RECT 0.00000 139.16000 0.21000 139.30000 ;
    END
  END wd_in[240]
  PIN wd_in[241]
    DIRECTION INPUT ;
    USE SIGNAL ;
    PORT
      LAYER metal4 ;
      RECT 0.00000 139.44000 0.21000 139.58000 ;
    END
  END wd_in[241]
  PIN wd_in[242]
    DIRECTION INPUT ;
    USE SIGNAL ;
    PORT
      LAYER metal4 ;
      RECT 0.00000 139.72000 0.21000 139.86000 ;
    END
  END wd_in[242]
  PIN wd_in[243]
    DIRECTION INPUT ;
    USE SIGNAL ;
    PORT
      LAYER metal4 ;
      RECT 0.00000 140.00000 0.21000 140.14000 ;
    END
  END wd_in[243]
  PIN wd_in[244]
    DIRECTION INPUT ;
    USE SIGNAL ;
    PORT
      LAYER metal4 ;
      RECT 0.00000 140.28000 0.21000 140.42000 ;
    END
  END wd_in[244]
  PIN wd_in[245]
    DIRECTION INPUT ;
    USE SIGNAL ;
    PORT
      LAYER metal4 ;
      RECT 0.00000 140.56000 0.21000 140.70000 ;
    END
  END wd_in[245]
  PIN wd_in[246]
    DIRECTION INPUT ;
    USE SIGNAL ;
    PORT
      LAYER metal4 ;
      RECT 0.00000 140.84000 0.21000 140.98000 ;
    END
  END wd_in[246]
  PIN wd_in[247]
    DIRECTION INPUT ;
    USE SIGNAL ;
    PORT
      LAYER metal4 ;
      RECT 0.00000 141.12000 0.21000 141.26000 ;
    END
  END wd_in[247]
  PIN wd_in[248]
    DIRECTION INPUT ;
    USE SIGNAL ;
    PORT
      LAYER metal4 ;
      RECT 0.00000 141.40000 0.21000 141.54000 ;
    END
  END wd_in[248]
  PIN wd_in[249]
    DIRECTION INPUT ;
    USE SIGNAL ;
    PORT
      LAYER metal4 ;
      RECT 0.00000 141.68000 0.21000 141.82000 ;
    END
  END wd_in[249]
  PIN wd_in[250]
    DIRECTION INPUT ;
    USE SIGNAL ;
    PORT
      LAYER metal4 ;
      RECT 0.00000 141.96000 0.21000 142.10000 ;
    END
  END wd_in[250]
  PIN wd_in[251]
    DIRECTION INPUT ;
    USE SIGNAL ;
    PORT
      LAYER metal4 ;
      RECT 0.00000 142.24000 0.21000 142.38000 ;
    END
  END wd_in[251]
  PIN wd_in[252]
    DIRECTION INPUT ;
    USE SIGNAL ;
    PORT
      LAYER metal4 ;
      RECT 0.00000 142.52000 0.21000 142.66000 ;
    END
  END wd_in[252]
  PIN wd_in[253]
    DIRECTION INPUT ;
    USE SIGNAL ;
    PORT
      LAYER metal4 ;
      RECT 0.00000 142.80000 0.21000 142.94000 ;
    END
  END wd_in[253]
  PIN wd_in[254]
    DIRECTION INPUT ;
    USE SIGNAL ;
    PORT
      LAYER metal4 ;
      RECT 0.00000 143.08000 0.21000 143.22000 ;
    END
  END wd_in[254]
  PIN wd_in[255]
    DIRECTION INPUT ;
    USE SIGNAL ;
    PORT
      LAYER metal4 ;
      RECT 0.00000 143.36000 0.21000 143.50000 ;
    END
  END wd_in[255]
  PIN addr_in[0]
    DIRECTION INPUT ;
    USE SIGNAL ;
    PORT
      LAYER metal4 ;
      RECT 0.00000 143.64000 0.21000 143.78000 ;
    END
  END addr_in[0]
  PIN addr_in[1]
    DIRECTION INPUT ;
    USE SIGNAL ;
    PORT
      LAYER metal4 ;
      RECT 0.00000 143.92000 0.21000 144.06000 ;
    END
  END addr_in[1]
  PIN addr_in[2]
    DIRECTION INPUT ;
    USE SIGNAL ;
    PORT
      LAYER metal4 ;
      RECT 0.00000 144.20000 0.21000 144.34000 ;
    END
  END addr_in[2]
  PIN addr_in[3]
    DIRECTION INPUT ;
    USE SIGNAL ;
    PORT
      LAYER metal4 ;
      RECT 0.00000 144.48000 0.21000 144.62000 ;
    END
  END addr_in[3]
  PIN addr_in[4]
    DIRECTION INPUT ;
    USE SIGNAL ;
    PORT
      LAYER metal4 ;
      RECT 0.00000 144.76000 0.21000 144.90000 ;
    END
  END addr_in[4]
  PIN addr_in[5]
    DIRECTION INPUT ;
    USE SIGNAL ;
    PORT
      LAYER metal4 ;
      RECT 0.00000 145.04000 0.21000 145.18000 ;
    END
  END addr_in[5]
  PIN we_in
    DIRECTION INPUT ;
    USE SIGNAL ;
    PORT
      LAYER metal4 ;
      RECT 0.00000 145.32000 0.21000 145.46000 ;
    END
  END we_in
  PIN clk
    DIRECTION INPUT ;
    USE SIGNAL ;
    PORT
      LAYER metal4 ;
      RECT 0.00000 145.60000 0.21000 145.74000 ;
    END
  END clk
  PIN ce_in
    DIRECTION INPUT ;
    USE SIGNAL ;
    PORT
      LAYER metal4 ;
      RECT 0.00000 145.88000 0.21000 146.02000 ;
    END
  END ce_in
  PIN VDD
    DIRECTION INOUT ;
    USE POWER ;
    PORT
      LAYER metal4 ;
      RECT 0.56000 2.24000 153.15000 2.80000 ;
      RECT 0.56000 6.72000 153.15000 7.28000 ;
      RECT 0.56000 11.20000 153.15000 11.76000 ;
      RECT 0.56000 15.68000 153.15000 16.24000 ;
      RECT 0.56000 20.16000 153.15000 20.72000 ;
      RECT 0.56000 24.64000 153.15000 25.20000 ;
      RECT 0.56000 29.12000 153.15000 29.68000 ;
      RECT 0.56000 33.60000 153.15000 34.16000 ;
      RECT 0.56000 38.08000 153.15000 38.64000 ;
      RECT 0.56000 42.56000 153.15000 43.12000 ;
      RECT 0.56000 47.04000 153.15000 47.60000 ;
      RECT 0.56000 51.52000 153.15000 52.08000 ;
      RECT 0.56000 56.00000 153.15000 56.56000 ;
      RECT 0.56000 60.48000 153.15000 61.04000 ;
      RECT 0.56000 64.96000 153.15000 65.52000 ;
      RECT 0.56000 69.44000 153.15000 70.00000 ;
      RECT 0.56000 73.92000 153.15000 74.48000 ;
      RECT 0.56000 78.40000 153.15000 78.96000 ;
      RECT 0.56000 82.88000 153.15000 83.44000 ;
      RECT 0.56000 87.36000 153.15000 87.92000 ;
      RECT 0.56000 91.84000 153.15000 92.40000 ;
      RECT 0.56000 96.32000 153.15000 96.88000 ;
      RECT 0.56000 100.80000 153.15000 101.36000 ;
      RECT 0.56000 105.28000 153.15000 105.84000 ;
      RECT 0.56000 109.76000 153.15000 110.32000 ;
      RECT 0.56000 114.24000 153.15000 114.80000 ;
      RECT 0.56000 118.72000 153.15000 119.28000 ;
      RECT 0.56000 123.20000 153.15000 123.76000 ;
      RECT 0.56000 127.68000 153.15000 128.24000 ;
      RECT 0.56000 132.16000 153.15000 132.72000 ;
      RECT 0.56000 136.64000 153.15000 137.20000 ;
      RECT 0.56000 141.12000 153.15000 141.68000 ;
      RECT 0.56000 145.60000 153.15000 146.16000 ;
    END
  END VDD
  PIN VSS
    DIRECTION INOUT ;
    USE GROUND ;
    PORT
      LAYER metal4 ;
      RECT 0.56000 0.00000 153.15000 0.56000 ;
      RECT 0.56000 4.48000 153.15000 5.04000 ;
      RECT 0.56000 8.96000 153.15000 9.52000 ;
      RECT 0.56000 13.44000 153.15000 14.00000 ;
      RECT 0.56000 17.92000 153.15000 18.48000 ;
      RECT 0.56000 22.40000 153.15000 22.96000 ;
      RECT 0.56000 26.88000 153.15000 27.44000 ;
      RECT 0.56000 31.36000 153.15000 31.92000 ;
      RECT 0.56000 35.84000 153.15000 36.40000 ;
      RECT 0.56000 40.32000 153.15000 40.88000 ;
      RECT 0.56000 44.80000 153.15000 45.36000 ;
      RECT 0.56000 49.28000 153.15000 49.84000 ;
      RECT 0.56000 53.76000 153.15000 54.32000 ;
      RECT 0.56000 58.24000 153.15000 58.80000 ;
      RECT 0.56000 62.72000 153.15000 63.28000 ;
      RECT 0.56000 67.20000 153.15000 67.76000 ;
      RECT 0.56000 71.68000 153.15000 72.24000 ;
      RECT 0.56000 76.16000 153.15000 76.72000 ;
      RECT 0.56000 80.64000 153.15000 81.20000 ;
      RECT 0.56000 85.12000 153.15000 85.68000 ;
      RECT 0.56000 89.60000 153.15000 90.16000 ;
      RECT 0.56000 94.08000 153.15000 94.64000 ;
      RECT 0.56000 98.56000 153.15000 99.12000 ;
      RECT 0.56000 103.04000 153.15000 103.60000 ;
      RECT 0.56000 107.52000 153.15000 108.08000 ;
      RECT 0.56000 112.00000 153.15000 112.56000 ;
      RECT 0.56000 116.48000 153.15000 117.04000 ;
      RECT 0.56000 120.96000 153.15000 121.52000 ;
      RECT 0.56000 125.44000 153.15000 126.00000 ;
      RECT 0.56000 129.92000 153.15000 130.48000 ;
      RECT 0.56000 134.40000 153.15000 134.96000 ;
      RECT 0.56000 138.88000 153.15000 139.44000 ;
      RECT 0.56000 143.36000 153.15000 143.92000 ;
    END
  END VSS
  OBS
    LAYER metal1 ;
    RECT 0 0 153.71000 147.00000 ;
    LAYER metal2 ;
    RECT 0 0 153.71000 147.00000 ;
    LAYER metal3 ;
    RECT 0 0 153.71000 147.00000 ;
    LAYER metal4 ;
    RECT 0 0 153.71000 147.00000 ;
  END
END cva6_sram_64x256

END LIBRARY
